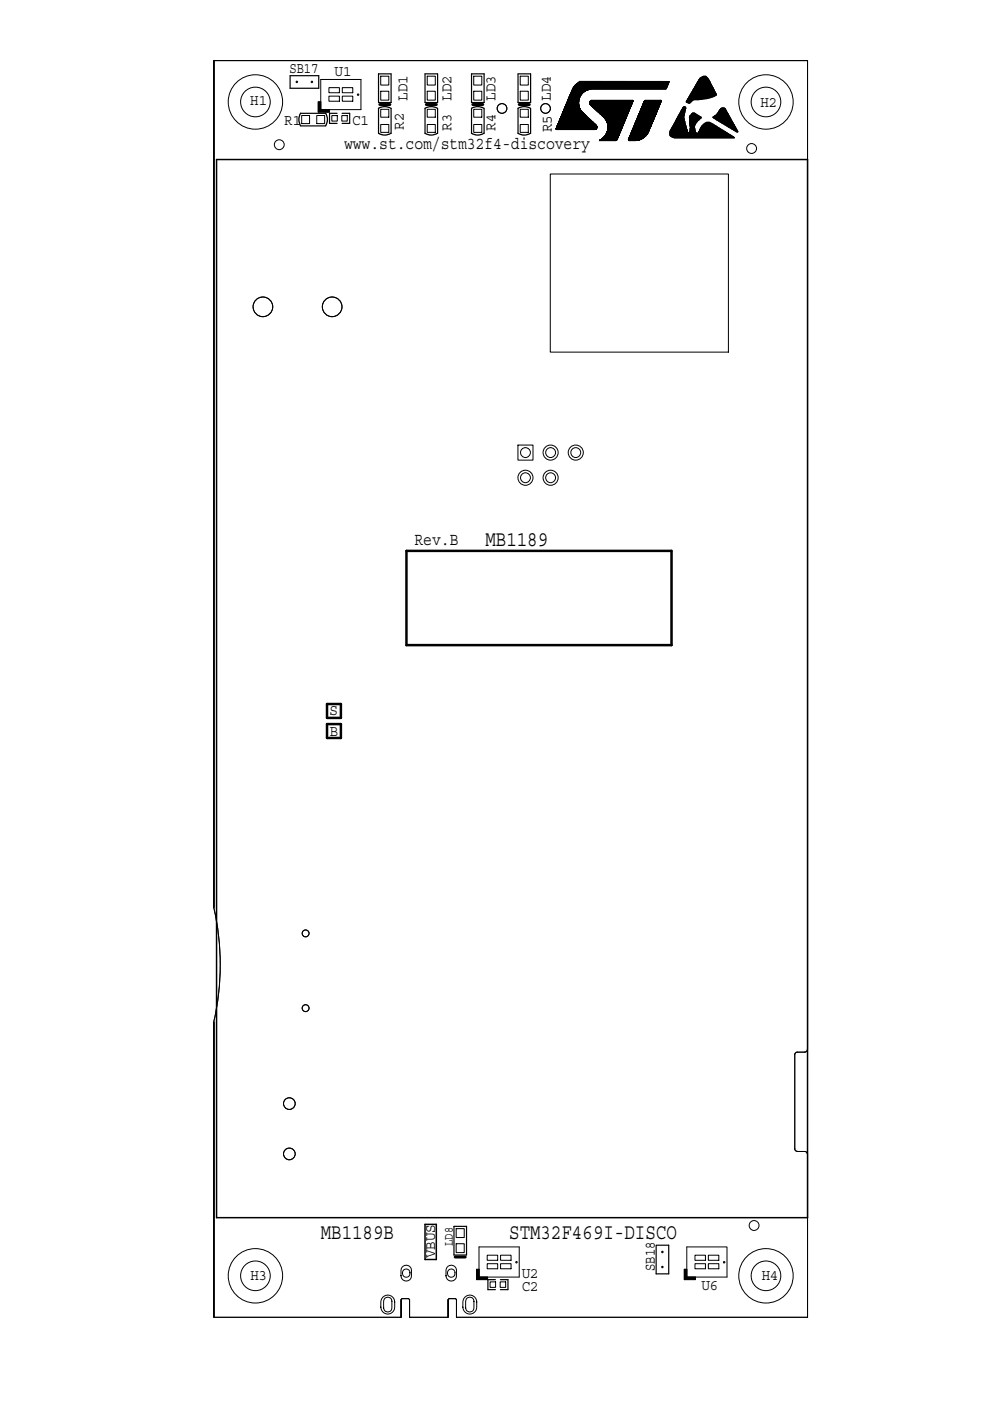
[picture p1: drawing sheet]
<svg xmlns="http://www.w3.org/2000/svg" width="210mm" height="297mm" viewBox="0 0 210 297" stroke-linecap="round" stroke-linejoin="round" font-family="sans-serif">
<defs><g id="words">
<g font-size="4.7">
<text x="103" y="115.7">MB1189</text>
<text x="68" y="262.8">MB1189B</text>
<text x="108" y="262.8">STM32F469I-DISCO</text>
</g>
<g font-size="3.8">
<text x="73" y="31.6">www.st.com/stm32f4-discovery</text>
<text x="87.9" y="115.5">Rev.B</text>
</g>
<g font-size="3.3">
<text x="61.4" y="15.5">SB17</text>
<text x="71" y="16">U1</text>
<text x="53.1" y="22.2">H1</text>
<text x="86.4" y="21.4" transform="rotate(-90 86.4 21.4)">LD1</text>
<text x="95.8" y="21.4" transform="rotate(-90 95.8 21.4)">LD2</text>
<text x="105.1" y="21.4" transform="rotate(-90 105.1 21.4)">LD3</text>
<text x="116.8" y="21.4" transform="rotate(-90 116.8 21.4)">LD4</text>
<text x="161.3" y="22.7">H2</text>
<text x="60.3" y="26.4">R1</text>
<text x="74.7" y="26.4">C1</text>
<text x="85.6" y="27.5" transform="rotate(-90 85.6 27.5)">R2</text>
<text x="95.8" y="27.8" transform="rotate(-90 95.8 27.8)">R3</text>
<text x="105.1" y="27.8" transform="rotate(-90 105.1 27.8)">R4</text>
<text x="117.1" y="28" transform="rotate(-90 117.1 28)">R5</text>
<text x="69.9" y="151.7">S</text>
<text x="69.9" y="156">B</text>
<text x="92.3" y="266.8" transform="rotate(-90 92.3 266.8)">VBUS</text>
<text x="138.9" y="269.5" transform="rotate(-90 138.9 269.5)">SB18</text>
<text x="53.1" y="271.3">H3</text>
<text x="110.7" y="271">U2</text>
<text x="110.7" y="273.7">C2</text>
<text x="148.8" y="273.4">U6</text>
<text x="161.6" y="271.3">H4</text>
</g>
<text font-size="2.8" x="96" y="264.1" transform="rotate(-90 96 264.1)">LD8</text>
</g></defs>
<g fill="none" stroke="#000" stroke-width=".21">
<path d="M45.4 12.8v179.6v-179.6M62.8 17.3h.3v.2h-.3zM66 17.3h.3v.2h-.3zM68 16.8h8.6v6.4h-8.6zM69.8 18.6h2.2v1.1h-2.2zM72.6 18.6h2.2v1.1h-2.2zM75.8 20h.3v.2h-.3zM80.8 19.3h1.7v1.9h-1.7zM80.8 16.2h1.7v1.8h-1.7zM90.6 19.3h1.7v1.9h-1.7zM90.6 16.2h1.7v1.8h-1.7zM100.5 19.3h1.7v1.9h-1.7z"/>
<path d="M100.5 16.2h1.7v1.8h-1.7zM110.3 19.3h1.8v1.9h-1.8zM110.3 16.2h1.8v1.8h-1.8zM121 20h.1M121.5 18.8h19.8M121.5 18.6h19.9M121.6 18.5h19.8M121.7 18.4h19.8M121.8 18.3h19.7M121.9 18.2h19.7M122 18.1h19.6M122.2 17.9h19.5"/>
<path d="M122.3 17.8h19.4M122.4 17.7h19.4M122.6 17.5h19.2M122.7 17.5h19.2M122.8 17.4h19.1M123.4 20h.1M123.4 19.9l-2.4 .1M123.4 19.9h-2.4M123.4 19.9h.1M123.5 19.9h.1M123.5 19.8l-2.5 .1M123.5 19.8h-2.4"/>
<path d="M123.5 19.8h.1M123.5 19.7h.1M123.6 19.7h-2.5M123.6 19.7h.1M123.7 19.6h.1M123.7 19.6h-2.6M123.8 19.6h-2.7M123.8 19.6h.1M123.8 19.5h-2.6M123.8 19.5h.1M123.9 19.5h.1M123.9 19.5h-2.7"/>
<path d="M124 19.4h.1M124 19.4h-2.8M124 19.3l-2.8 .1M124.1 19.3h.1M124.1 19.3h-2.9M124.2 19.3h.1M124.2 19.2l-2.9 .1M124.2 19.2h.1M124.3 19.2h.1M124.3 19.2h-3M124.4 19.2h.1M124.5 19.1l-3.2 .1"/>
<path d="M124.5 19.1h.1M124.6 19.1h.1M124.6 19.1h-3.3M124.7 19h.1M124.8 19l-3.5 .1M124.8 19h.1M124.9 19h.1M125 19h-3.6M125 19h.1M125.3 18.9h-3.9M141.3 18.9h-19.9M141.4 18.7h-19.9"/>
<path d="M141.4 18.6h-19.8M141.4 18.5l-19.8 .1M141.5 18.3h-19.7M141.6 18.2h-19.8M141.6 18.1l-19.7 .1M141.7 18h-19.7M141.7 17.9l-19.7 .1M141.7 17.9h-19.6M141.7 17.8h-19.5M141.8 17.7h-19.4M141.9 17.6h-19.4M141.9 17.3h-19"/>
<path d="M146.5 19.9h5.4l-5.4 .1h5.5v.2h-5.6M146.7 19.5h5l-5 .1 5 .1h-5.1l5.2 .1h-5.2h5.2M146.9 19.2h4.6l-4.6 .1h4.7h-4.8M147.1 18.9h4.3l-4.4 .1h4.4l-4.4 .1h4.5h-4.6M147.2 18.6l4.1 .1h-4.1M147.3 18.5h3.9l-3.9 .1M147.7 17.9h3.1h-3.2l3.3 .1-3.3 .1h3.3l-3.4 .1h3.5h-3.5M147.8 17.5h2.9l-2.9 .1M148.1 17.2h2.4l-2.5 .1 2.6 .1h-2.6l2.6 .1h-2.7M148.2 17l2.2 .1h-2.2M148.3 16.8l2 .1-2.1 .1h2.2M148.3 16.7l2 .1h-2"/>
<path d="M148.4 16.7h1.8M148.5 16.5l1.6 .1h-1.7h1.7M148.6 16.5h1.4M148.7 16.4h1.3M148.8 16.4h1.1M148.9 16.3h1M149 16.3h.8M149.1 16.2h.7M150.5 17.1h-2.4l2.4 .1M150.7 17.6l-2.9 .1h2.9M150.8 17.7h-3.1l3.1 .1M151 18.3h-3.6h3.6"/>
<path d="M151.1 18.4h-3.7l3.8 .1h-3.9M151.3 18.8h-4.1h4.1M151.6 19.4l-4.8 .1h4.8M171.3 12.8h-125.9h125.9M171.3 12.8v209.7M64 24.5h1.7v1.7h-1.7zM67.2 24.5h1.7v1.7h-1.7zM67.5 23.7h2.3M67.5 23.6h2.3M67.5 23.5h2.3M67.5 23.4h2.3M67.5 23.3h2.3"/>
<path d="M67.5 23.2h.5M67.5 23.1h.5M67.5 23h.5M67.5 22.9h.5M67.5 22.8h.5M67.5 22.7h.5M67.5 22.6h.5M67.5 22.5h.5M67.5 22.4h.5M67.5 22.3h.5M67.5 22.2h.5M67.5 22.1h.5"/>
<path d="M67.5 22h.5M67.5 21.9h.5M67.5 21.8h.5M67.5 21.7h.5M67.5 21.6h.5M68 23.2v-1.6h-.5v2.1h2.3v-.5h-2.3M69.8 20.4h2.2v1.1h-2.2zM70.4 24.5h1.1v1.2h-1.1zM72.5 24.5h1.2v1.2h-1.2zM72.6 20.4h2.2v1.1h-2.2zM80.8 23.2h1.7v1.6h-1.7zM80.8 26.4h1.7v1.7h-1.7z"/>
<path d="M90.6 23.2h1.7v1.6h-1.7zM90.6 26.4h1.7v1.7h-1.7zM100.5 23.2h1.7v1.6h-1.7zM100.5 26.4h1.7v1.7h-1.7zM110.3 23.2h1.8v1.6h-1.8zM110.3 26.4h1.8v1.7h-1.8zM116.7 36.9h37.8v37.8h-37.8zM118 27.2h8.6M118 27.4h8.4M118 27.3h.1M118 27.2h.1M118 27.4h.1"/>
<path d="M118 27.5h8.3M118 27.1h8.6M118 27h8.6M118.1 26.9h8.5M118.1 27h.1M118.1 26.9h.1M118.1 26.8h8.5M118.2 26.7h8.4M118.2 26.8h.1M118.2 26.7h.1M118.2 26.6h8.3M118.2 26.6h.1"/>
<path d="M118.3 26.5h8.1M118.3 26.5h.1M118.3 26.4h.1M118.3 26.4h8M118.3 26.3h7.9M118.4 26.2l7.8 .1M118.4 26.3h.1M118.4 26.2h.1M118.4 26.2h7.6M118.4 26.2h7.7M118.4 26.1h7.5M118.5 26h7.3"/>
<path d="M118.5 26h.1M118.5 25.9l7.3 .1M118.5 25.8h7.2M118.5 25.9h7.2M118.6 25.7h7M118.6 25.8h7M118.6 25.8h.1M118.6 25.7h.1M118.6 25.7h6.9M118.6 25.6h6.9M118.7 25.5h6.6M118.7 25.5l6.7 .1"/>
<path d="M118.7 25.5h.1M118.7 25.4h6.5M118.7 25.4h.1M118.7 25.3l6.5 .1M118.8 25.3h6.3M118.8 25.2h6.2M118.8 25.2l6.3 .1M118.8 25.3h.1M118.8 25.2h.1M118.8 25.1h6.1M118.8 25.1h.1M118.9 25.1h6"/>
<path d="M118.9 25h5.9M118.9 24.9h5.8M119 24.8h5.6M119 24.7l5.5 .1M119 24.7h5.5M119 24.7h.1M119 24.6l5.4 .1M119.1 24.6h5.2M119.1 24.6h5.3M119.1 24.5h5.1M119.1 24.5h.1M119.1 24.4l5.1 .1"/>
<path d="M119.1 24.4h.1M119.1 24.4h5M119.2 24.3l4.9 .1M119.2 24.3h4.8M119.2 24.3h.1M119.2 24.2h4.7M119.2 24.2h.1M119.3 24.1h4.6M119.3 24.1h4.5M119.3 24h4.5M119.3 24h4.4M119.3 24h.1"/>
<path d="M119.3 23.9h4.4M119.3 23.9h.1M119.4 23.9h4.2M119.4 23.8h4.1M119.4 23.7l4.1 .1M119.4 23.8h.1M119.4 23.7h4M119.4 23.7h.1M119.5 23.6h3.8M119.5 23.5h3.8M119.5 23.5h.1M119.5 23.4h3.7"/>
<path d="M119.5 23.5h3.7M119.5 23.4h.1M119.6 23.3h3.5M119.6 23.2h3.5M119.6 23.3h.1M119.6 23.2h.1M119.7 23.2h.1M119.7 23.2h3.4M119.7 23.1h3.3M119.7 23h3.3M119.7 23.1h.1M119.7 23h.1"/>
<path d="M119.8 22.9h.1M119.8 22.9h3.1M119.8 22.8h3.1M119.8 22.8h.1M119.8 22.7h.1M119.8 22.7h3.1M119.9 22.7h.1M119.9 22.6h.1M119.9 22.6h3M119.9 22.6h2.9M119.9 22.5h2.9M119.9 22.5h.1"/>
<path d="M120 22.5h2.8M120 22.4h2.8M120 22.3h2.8M120 22.2l2.8 .1M120 22.3h.1M120.1 22.2h2.6M120.1 22.1h2.6M120.1 22h2.6M120.1 22h.1M120.2 22h2.5M120.2 21.9h2.5M120.2 21.8h2.5"/>
<path d="M120.2 21.7h2.5M120.2 21.8h.1M120.3 21.7h2.4M120.3 21.6h2.4M120.3 21.5h2.4M120.4 21.5h.1M120.4 21.4h2.3M120.4 21.5h2.3M120.4 21.4h2.4M120.4 21.3h2.4M120.4 21.3h.1M120.4 21.2h2.4"/>
<path d="M120.5 21.3h.1M120.5 21.2h.1M120.5 21.2h2.3M120.5 21.1h2.3M120.5 21h2.3M120.5 21.1h.1M120.5 21h.1M120.6 21h2.2M120.6 21h.1M120.6 20.9h2.3M120.6 20.9h.1M120.6 20.8h2.3"/>
<path d="M120.6 20.8h.1M120.7 20.7h2.2M120.7 20.8h.1M120.7 20.7h.1M120.7 20.6h2.3M120.7 20.5h2.3M120.8 20.5h.1M120.8 20.6h.1M120.8 20.5h2.2M120.8 20.4h2.3M120.8 20.3h2.3M120.9 20.3h.1"/>
<path d="M120.9 20.2h.1M120.9 20h2.4M121 20.1h.1M122.7 21.8h.1M122.7 21.7h.1M122.7 22h.1M122.7 21.9h.1M122.7 21.6h.1M122.7 21.5h.1M122.7 22.2h.1M122.7 22.1h.1M122.7 21.6l-2.4 .1"/>
<path d="M122.7 21.4h.1M122.8 22.4h-2.8M122.8 22.5h.1M122.8 22.4h.1M122.8 21.2h.1M122.8 21.1h.1M122.8 21.1h-2.3M122.8 22.6h.1M122.8 21h.1M122.9 21h-2.3M122.9 22.7h.1M122.9 22.6h.1"/>
<path d="M122.9 21h.1M122.9 20.9h.1M122.9 20.9h-2.3M122.9 22.9h.1M122.9 22.8h.1M122.9 20.8h.1M122.9 20.7h.1M123 20.7h-2.3M123 20.6h-2.3M123 20.6h.1M123 23.1h.1M123 20.5h.1"/>
<path d="M123 23.2h.1M123.1 20.3h.1M123.1 23.3h.1M123.2 20.3h-2.4M123.2 20.2h-2.3M123.2 20.2h.1M123.2 23.5h.1M123.3 20.1h.1M123.3 23.5h.1M123.3 20.1h-2.4M123.3 20l-2.4 .1M123.3 20h.1"/>
<path d="M123.3 23.6h.1M123.4 23.6h.1M123.4 23.7h.1M123.5 23.8h.1M123.6 23.9h.1M123.7 23.9h.1M123.7 24h.1M123.8 24h.1M123.8 24.1h.1M123.9 24.1h.1M124 24.2h.1M124.1 24.3h.1"/>
<path d="M124.1 24.4h.1M124.2 24.4h.1M124.2 24.5h.1M124.3 24.5h.1M124.4 24.6h.1M124.9 25.1h.1M125 25.1h.1M125 25.2h.1M125.1 21.8h9M125.1 21.8h.1M125.1 21.9h.1M125.1 21.9h9"/>
<path d="M125.1 25.3h.1M125.1 21.7h9.1M125.1 22h8.9zM125.1 22h8.9M125.1 21.9h8.9M125.1 21.6h9.1M125.1 22.1h8.9M125.2 22.1h8.8M125.2 21.5h.1M125.2 22.1h.1M125.2 25.4h.1M125.2 21.5h9"/>
<path d="M125.2 21.4h9.1M125.2 22.2h8.8M125.2 22.2h8.7M125.3 22.2h8.6M125.3 22.2h.1M125.3 25.4h.1M125.3 21.4h8.9M125.3 22.3h8.6M125.3 25.5h.1M125.3 21.3h8.9M125.4 22.4h8.5h-8.5M125.4 21.3h.1"/>
<path d="M125.4 22.4h.1M125.4 25.5h.1M125.4 25.6h.1M125.4 22.4h8.5M125.5 21.3h8.7M125.5 22.5h8.3M125.5 21.3h.1M125.5 25.7h.1M125.5 22.5h.1M125.6 22.5h8.2M125.6 22.5h.1M125.6 22.6h8.2h-8.2"/>
<path d="M125.6 25.8h.1M125.7 22.6h8.1M125.7 22.6h.1M125.7 25.8h.1M125.7 22.7h8.1M125.7 25.9h.1M125.8 22.7h8M125.8 22.7h7.9M125.8 22.7h.1M125.8 25.9h.1M125.8 22.8h7.9M125.8 26h.1"/>
<path d="M125.8 22.8h7.9h-7.8M125.9 22.8h7.8zM125.9 26h.1M125.9 26.1h.1M126 22.9h7.7M126 22.9l7.6 .1zM126 22.9h.1M126 26.1h.1M126.1 23h7.5M126.1 23.1h7.5zM126.1 23h.1M126.1 26.2h.1"/>
<path d="M126.2 23.1h7.4M126.2 23.1h.1M126.2 26.3h.1M126.2 27.5h.1M126.2 23.2h7.4M126.2 26.4h.1M126.3 23.2h7.2M126.3 26.4h.1M126.3 23.2h.1M126.3 26.5h.1M126.3 27.4h.1M126.4 23.3h7.1"/>
<path d="M126.4 26.5h.1M126.4 27.4h.1M126.4 23.3h.1M126.4 26.6h.1M126.5 27.3l-8.5 .1M126.5 23.4h7M126.5 27.3h-8.5M126.5 26.6h.1M126.5 27.3h.1M126.5 23.4h.1M126.5 26.7h.1M126.6 27.2l-8.6 .1"/>
<path d="M126.6 27.2h.1M126.6 23.5h6.8M126.6 26.7h.1M126.6 26.9h-8.5M126.6 26.8h.1M126.6 27.1h.1M126.6 27h.1M126.6 26.9h.1M126.6 23.5h.1M126.7 23.6h6.7M126.7 23.6h6.7h-6.7M126.7 23.6h.1"/>
<path d="M126.8 23.6h6.5M126.8 23.7h6.5M126.8 23.7h.1M126.9 23.7h6.4M126.9 23.8h6.4M126.9 23.8h.1M127 23.8h6.3M127 23.9h6.3M127.1 23.9h6.1M127.1 24h6.1M127.1 24h.1M127.2 24h6"/>
<path d="M127.2 29.8h3.5M127.2 29.8h3.4M127.2 24.1h6M127.2 24.1h.1M127.2 29.8h.1M127.3 24.1h.1M127.3 29.7h.1M127.3 24.1h5.9M127.3 24.1h5.8M127.3 24.2h5.8M127.3 24.2h.1M127.4 24.2h5.7"/>
<path d="M127.4 29.6h3.4l-3.5 .1M127.4 24.3h5.7M127.4 24.3h5.7zM127.4 29.6h.1M127.5 24.3h5.6M127.6 24.4h5.4zM127.6 24.4h.1M127.6 29.5h.1M127.6 29.5h3.3M127.6 24.4h5.4M127.7 29.4h.1M127.7 24.5h5.3z"/>
<path d="M127.7 24.5h.1M127.7 29.4h3.2h-3.3M127.7 24.5h5.3M127.7 29.4h3.3M127.8 24.6h.1M127.8 29.4h.1M127.8 24.6h5.1h-5.1M127.8 24.6h5.1M127.8 29.3h3.2M127.9 24.6h.1M127.9 29.3h.1M127.9 24.7h5"/>
<path d="M127.9 29.3h3.1M128 29.2h.1M128 29.2h3.1M128 24.7h.1M128 24.7h4.9M128 24.8h4.9M128 29.1h3.1M128.1 24.8h.1M128.1 29.1h.1M128.1 24.8l4.7 .1h-4.7M128.1 29l3 .1h-3M128.1 24.9h4.7"/>
<path d="M128.2 29h.1M128.2 24.9h.1M128.2 29h2.9M128.2 25h4.6M128.2 28.9h3M128.2 25.1h4.6M128.3 25.1h.1M128.3 25h.1M128.3 28.9h.1M128.3 25.1h4.4M128.3 28.8h2.9M128.3 25.2h4.4"/>
<path d="M128.3 28.7h2.9M128.4 25.2h.1M128.4 28.7h.1M128.4 25.2h4.3M128.4 28.7h2.8M128.4 28.7h2.9M128.4 25.3h4.3M128.4 28.6h2.9M128.5 28.5h2.8zM128.5 28.6h.1M128.5 25.4h.1M128.5 25.4h4.1"/>
<path d="M128.5 28.5h2.8M128.5 25.5h4.1M128.6 28.4h2.8M128.6 28.4h.1M128.6 25.5h.1M128.6 25.6h3.9M128.6 28.3h2.8M128.7 28.2h2.7M128.7 28.2h.1M128.7 28.1h2.8M128.7 25.7h.1M128.7 25.8h3.8"/>
<path d="M128.7 25.8h3.7M128.7 25.9h3.7M128.8 27.9h2.8M128.8 25.9h3.6M128.8 28h.1M128.8 27.9h.1M128.8 25.9h.1M128.8 26h3.6M128.8 27.8h2.8M128.8 26.1h3.5M128.9 27.6h2.8M128.9 26.2l3.3 .1h-3.3"/>
<path d="M128.9 26.2h3.4M128.9 27.7h.1M128.9 27.6h.1M128.9 26.2h.1M128.9 27.5h2.8M128.9 26.3h3.3M128.9 26.5h3.2M128.9 27.3h2.9M128.9 26.4h3.3M128.9 27.2h2.9M128.9 27.2h3M128.9 26.8h3.2"/>
<path d="M128.9 26.6h3.2M128.9 26.7h3.2M129 27h3M129 26.9h3M129 27.1h2.9M129 26.8h3M129 27.1h.1M129 27h.1M129 26.9h.1M129 26.8h.1M130.5 29.8h.1M130.6 29.8h.1"/>
<path d="M130.7 29.7h.1M130.8 29.7h.1M130.8 29.7h-3.6M130.9 29.7h.1M130.9 29.6h.1M130.9 29.6h-3.5M130.9 29.5h-3.4M130.9 29.5h.1M131 29.4h.1M131 29.3h.1M131 29.3h-3.2h3.2M131 29.2h.1"/>
<path d="M131.1 29.2h-3.2M131.1 29.1h.1M131.1 29.2h.1M131.1 29h-3M131.1 29h.1M131.2 28.9h.1M131.2 28.9h-3M131.3 28.7h.1M131.3 28.6h-2.9M131.4 28.5h.1M131.4 28.4h.1M131.4 28.4h-2.9"/>
<path d="M131.5 28.2h.1M131.5 28l-2.8 .1M131.6 28h-2.8M131.6 28h.1M131.6 27.9h.1M131.7 27.8h.1M131.7 27.7h.1M131.7 27.7h-2.9M131.7 27.6h.1M131.8 27.5h-2.9h2.8M131.8 27.5h.1M131.8 27.4h.1"/>
<path d="M131.8 27.4h-2.9h2.9M131.9 27.3h.1M131.9 27.2h.1M131.9 27.1h.1M131.9 27.1h-3M132 27h.1M132 26.9h.1M132 26.9h-3M132.1 26.8h.1M132.1 26.7h.1M132.1 26.6l-3.2 .1M132.1 26.5l-3.2 .1"/>
<path d="M132.2 26.5h.1M132.2 26.4h.1M132.2 26.4h-3.3l3.3 .1M132.2 26.4h-3.3h3.3M132.3 26.2h.1M132.3 26.1h-3.5M132.4 26h.1M132.4 25.9h.1M132.5 25.8h.1M132.5 25.7h.1M132.5 25.7h-3.8M132.5 25.6h.1"/>
<path d="M132.6 25.5h.1M132.6 25.4h.1M132.7 25.3l-4.2 .1M132.7 25.3h.1M132.7 25.2h.1M132.8 25h.1M132.8 24.9h.1M132.9 24.7h.1M133 24.5h.1M133 24.4h.1M133.1 24.3h.1M133.1 24.2h.1"/>
<path d="M133.1 24.1h.1M133.2 24.1h.1M133.2 24h.1M133.2 23.9h.1M133.3 29.7h2.2M133.3 23.8h.1M133.3 29.7h.1M133.3 29.6h.1M133.3 23.7h.1M133.3 29.7h2M133.3 29.7h2.1M133.3 29.5h2.7"/>
<path d="M133.3 29.8h1.9M133.3 29.5h2.8M133.4 29.8h1.6M133.4 29.4h.1M133.4 29.3h.1M133.4 23.5h.1M133.4 23.4h.1M133.5 29.8h1.2M133.5 23.4h.1M133.5 29.1h.1M133.5 23.3h.1M133.5 23.2h.1"/>
<path d="M133.6 28.8h3.4zM133.6 23h.1M133.6 28.8h.1M133.6 22.9h.1M133.7 28.7h3.4M133.7 28.6h3.5M133.7 28.5h3.5zM133.7 22.8h.1M133.7 28.6h.1M133.8 22.7h.1M133.8 22.6h.1M133.8 28.5h3.4"/>
<path d="M133.8 28.3h3.5M133.8 28.3h3.6M133.8 28.2h3.6zM133.8 22.5h.1M133.8 28.3h.1M133.9 22.4h.1M133.9 28.2h3.5h-3.5M133.9 28.1h3.6M133.9 22.3h.1M133.9 28.1h.1M133.9 28h3.6M133.9 22.2h.1"/>
<path d="M134 22.2h.1M134 28h3.5M134 27.9h3.5M134 27.9h3.6M134 27.9h.1M134 27.8h.1M134 22.1h.1M134 22h.1M134 21.9h.1M134.1 27.7h3.5M134.1 21.9h.1M134.1 27.7h3.6"/>
<path d="M134.1 27.6h3.6M134.1 21.8l-9 .1M134.1 21.8h.1M134.1 27.6h.1M134.2 21.7l-9.1 .1M134.2 21.3h.1M134.2 21.7h.1M134.2 27.6h3.5M134.2 27.5h3.5M134.2 27.4h3.6M134.2 27.3h3.6M134.2 21.5h-9.1"/>
<path d="M134.2 27.3h3.7zM134.2 21.4h.1M134.2 21.5h.1M134.2 27.3h.1M134.3 21.4h.1M134.3 27.3h3.5h-3.6M134.3 27.2h3.6M134.3 27.1h3.6M134.3 27.1h.1M134.4 27.1h3.5M134.4 27h3.5M134.4 27h3.6"/>
<path d="M134.4 26.9h3.6M134.4 26.8h3.6M134.5 26.8h.1M134.5 26.8h3.5M134.5 26.7h3.6M134.5 26.6h3.6M134.6 26.5l3.6-.1zM134.6 26.6h.1M134.6 26.5h3.5M134.6 26.4h3.6M134.6 26.3h3.6M134.7 26.3h.1"/>
<path d="M134.7 26.2h3.6M134.7 26.1h3.6M134.7 29.8h.1M134.7 26.1h.1M134.8 26l3.6-.1zM134.8 26.1h.1M134.8 26h3.5M134.8 25.8h3.6M134.8 25.9h3.6M134.9 25.9h.1M134.9 25.8h.1M134.9 25.8h3.5"/>
<path d="M134.9 25.8h3.6M134.9 25.6h3.6M134.9 25.7h3.6M135 25.6h.1M135 25.5h3.6zM135 25.5h3.5M135 25.3h3.6M135.1 25.3l3.6-.1zM135.1 25.3h.1M135.1 29.8h.1M135.1 25.4h.1M135.1 25.3h3.5"/>
<path d="M135.1 25.1h3.6M135.2 25h3.6zM135.2 25.1h.1M135.2 25h3.5M135.2 24.9h3.6M135.3 24.8h.1M135.3 24.8h3.6M135.3 24.7h3.6M135.3 24.6h3.6M135.4 24.6h.1M135.4 24.5h3.6M135.4 24.4h3.6"/>
<path d="M135.5 24.4h.1M135.5 29.7h.1M135.5 24.3h3.6M135.5 24.3h.1M135.6 24.1h3.5M135.6 24.1h.1M135.6 24h3.6zM135.6 24.1h3.5h-3.5M135.6 24h3.6M135.7 23.9h.1M135.7 23.8h3.6M135.7 29.6h.1"/>
<path d="M135.7 29.6l-2.4 .1M135.7 23.7h3.6M135.8 23.6h.1M135.8 29.6h.1M135.8 23.5h3.6M135.8 29.6h-2.5M135.9 23.3h3.5M135.9 23.4h.1M135.9 23.3h.1M135.9 23.3h3.6h-3.6M135.9 29.5h.1M135.9 23.3h3.6"/>
<path d="M135.9 23.2h3.6M136 29.5h-2.7h2.6M136 23.2h3.5M136 23.1h3.6M136 23.1h.1M136 23.1h3.6h-3.6M136 29.5h.1M136.1 22.9h3.5M136.1 22.9h3.6M136.1 22.8h.1M136.1 22.8h3.6h-3.6M136.1 22.8h3.6"/>
<path d="M136.1 29.4h.1M136.1 22.7h3.6M136.2 29.4h-2.9h2.8M136.2 29.4h.1M136.2 22.6h.1M136.2 22.6h3.6M136.2 22.5h.1M136.2 22.5h3.6h-3.6M136.2 22.5h3.6M136.2 22.4h3.6M136.3 29.4h-2.9M136.3 29.4h.1"/>
<path d="M136.3 22.4h.1M136.3 29.3h.1M136.3 22.3h.1M136.3 22.3h3.6M136.3 22.2h3.6M136.4 22.2h3.5M136.4 22.2h3.6M136.4 29.3h-3M136.4 22.1h.1M136.4 29.3h.1M136.4 22.1h3.6M136.4 29.3h-3h3"/>
<path d="M136.5 21.9h3.5M136.5 21.9h3.6M136.5 21.8l3.6-.1zM136.5 21.9h.1M136.5 29.2h-3.1h3.1M136.5 21.8h3.6M136.5 29.2h.1M136.6 29.1l-3.2 .1h3.1M136.6 21.7h3.6M136.6 21.7h3.5M136.6 21.6h3.6M136.6 21.6h.1"/>
<path d="M136.6 21.5h3.6M136.6 29.1h.1M136.7 29.1h-3.2M136.7 21.5h3.5M136.7 21.4h3.5M136.7 29l-3.2 .1M136.7 21.4h.1M136.7 29h.1M136.8 29h-3.3h3.3M136.8 21.3h3.4M136.8 21.3h.1M136.8 29h.1"/>
<path d="M136.8 28.9h.1M136.8 28.9l-3.2 .1M136.9 28.9h-3.3M136.9 21.3h3.2M136.9 21.3h.1M136.9 28.9h.1M136.9 28.8l-3.3 .1M136.9 28.8h.1M137 28.8h.1M137 28.7h.1M137.1 28.7h-3.5h3.4M137.1 28.7h.1"/>
<path d="M137.1 28.6h.1M137.1 28.6l-3.4 .1M137.2 28.6h.1M137.2 28.5h.1M137.3 28.4h-3.5M137.3 28.4h.1M137.4 28.3h.1M137.4 28.2h.1M137.5 28.1h.1M137.5 28.1l-3.6 .1M137.5 28h.1M137.5 27.9h.1"/>
<path d="M137.6 27.9h.1M137.6 27.9h-3.6M137.6 27.8h-3.6M137.6 27.8h.1M137.6 27.7h.1M137.7 27.7h.1M137.7 27.6h.1M137.7 27.5h.1M137.8 27.5h.1M137.8 27.5h-3.6h3.5M137.8 27.4h.1M137.9 27.2h-3.6"/>
<path d="M138 27h.1M138 26.9h.1M138 26.9h-3.6M138 26.8h.1M138.1 26.7h.1M138.1 26.7h-3.6M138.1 26.5l-3.6 .1M138.2 26.5h.1M138.2 26.4h.1M138.2 26.4h-3.6M138.3 26.3h.1M138.3 26.2h-3.6l3.5 .1"/>
<path d="M138.3 26.2h.1M138.3 26l-3.6 .1M138.4 26h.1M138.5 25.8h.1M138.5 25.7h.1M138.5 25.7h-3.6h3.6M138.6 25.5h.1M138.6 25.6h.1M138.6 25.4l-3.6 .1M138.6 25.4h.1M138.6 25.4h-3.6M138.7 25.3h.1"/>
<path d="M138.7 25.2h.1M138.7 25.1h.1M138.7 25.2h-3.6M138.7 25.1h-3.6M138.8 25h.1M138.8 24.8l-3.6 .1M138.9 24.8h-3.6M138.9 24.8h.1M138.9 24.7h.1M138.9 24.6l-3.6 .1M139 24.5l-3.6 .1M139 24.5h.1"/>
<path d="M139.1 24.3h.1M139.1 24.2h.1M139.1 24.2h-3.6M139.2 24h.1M139.2 23.9h.1M139.2 23.9h-3.6M139.3 23.9h-3.6M139.3 23.9h.1M139.3 23.8h.1M139.3 23.7h.1M139.3 23.6l-3.6 .1M139.4 23.6h-3.6"/>
<path d="M139.4 23.6h.1M139.4 23.5h-3.6l3.6 .1M139.4 23.5h.1M139.4 23.4h.1M139.4 23.4h-3.6M139.5 23.3h.1M139.5 23.2h.1M139.6 23.1h.1M139.6 23h.1M139.6 23h-3.6h3.6M139.6 22.9l-3.6 .1M139.7 22.8h.1"/>
<path d="M139.7 22.7h.1M139.7 22.7h-3.6M139.8 22.6h-3.6M139.8 22.5h.1M139.9 22.4h-3.6M139.9 22.3h-3.6M139.9 22.3h.1M139.9 22.2h.1M140 22.1h-3.6M140 22.1h.1M140 22h.1M140 22h-3.6h3.6"/>
<path d="M140 21.9h.1M140.1 21.8l-3.6 .1M140.1 21.8h.1M140.1 21.3h.1M140.1 21.7h.1M140.2 21.3h.1M140.2 21.6h.1M140.2 21.5h.1M140.2 21.4h.1M142 28.2h5.8M142 28.6h12.9M142 28.2h12.3"/>
<path d="M142 28.4h12.6M142 27.9h3.8M142 28h3.9M142 28.1h5.6M142 28.6h13M142 28.5h12.8M142 28.3h12.5M142 28.1h3.9M142 28.5h12.7M142.1 27.9h3.7M142.1 27.8h3.7v.2h-3.8M142.1 28.7h13.1"/>
<path d="M142.1 28.7h12.9M142.2 27.7h3.6M142.2 28.8h13.1M142.2 27.6h3.6v.2h-3.6l3.6-.1M142.2 28.9h13.2M142.3 28.9h13.2M142.3 27.5l3.4 .1h-3.4M142.3 27.5h3.4M142.4 27.3l3.3 .1h-3.4M142.4 29h13.2M142.4 27.2l3.2 .1h-3.2M142.5 29h13.1"/>
<path d="M142.5 27.1h3.1l-3.1 .1M142.5 27h3.1h-3.1M142.5 27.1h3.1M142.6 29.1h13.1M142.6 26.9h2.9M142.7 26.8l2.8 .1h-2.9M142.7 29.1h13l-12.8 .1M142.7 26.6l2.8 .2M142.9 26.3l2.5 .1-2.5 .1M143 26.2l2.4 .1M143 29.3h12.7M143.1 26.1h2.2l-2.3 .1"/>
<path d="M143.3 25.7h1.9v.2l-2.1 .1M143.3 25.7h.1M143.3 25.5l1.9 .1h-1.9M143.4 25.4h1.7M143.4 25.4h.1M143.6 25.1h1.5h-1.6l1.6 .2h-1.6h1.6v.2M143.7 24.8h1.3h-1.3l1.3 .1h-1.3M143.8 24.7h1.2h-1.2M144.1 24.2h1.1l-1.1 .1h1.1M144.3 23.8h.9v.1h-1l1 .1-1 .1h1M144.7 23.1h.8M144.8 23h.7h-.7"/>
<path d="M144.8 22.8l.7 .1M144.9 22.7l.5 .1h-.5M145 22.6h.4M145 22.6h.3M145 25h-1.4h1.5M145.1 24.5h-1.2l1.2 .1h-1.3h1.3M145.1 24.3l-1.1 .1M145.2 23.8h-.9l.9 .1M145.2 25.8h-2M145.3 23.5l-.9 .1 .8 .1h-.8M145.4 23.3l-.9 .2M145.4 23.1h-.7l.7 .1-.8 .1h.8"/>
<path d="M145.5 26.5v.1M145.5 26.5l-2.8 .1M145.6 21.7h.9M145.6 21.4h1.2M145.7 21.7h.8M145.8 21.2h2.5M145.8 21.8h.6M145.9 21.8h.5M146 20.8h4.6M146 20.7h4.7M146.1 21.9h.2M146.1 20.7h4.7"/>
<path d="M146.2 20.5h5.1M146.2 24.8l2.5 .1h-2.5M146.3 24.8h2.4M146.3 25.6h.1M146.3 25.9h1.5M146.3 25.5h1.9M146.3 25.3h2.1M146.3 25.2h2.2M146.3 25.4h.1M146.3 25.5h.1M146.3 25.1h2.4M146.3 25.1h2.3"/>
<path d="M146.3 27.9h1.2h-1.2M146.3 26.3h1.2M146.3 26.2l1.2 .1M146.3 26.3v.1M146.3 26.4v.1M146.4 24.5h1.8M146.4 27.6h1h-1v.2h1M146.4 27.7h1h-1M146.4 26.7h.9v.2h-.9h.9M146.4 26.6v.1M146.4 26.8h.1M146.4 24.5h1.7"/>
<path d="M146.4 27h.9v.2l-.9 .1h1v.2h-1h1M146.5 24.4h1.6M146.5 24.4h1.5M146.6 24.3h1.2M146.6 24.3h1.1M146.6 21.6h-1h1M146.7 24.1h.8M146.7 21.5h-1.1h1.1M146.8 24h.6M146.9 23.9h.4M146.9 21.3h-1.2l1.1 .1M147 21.2h-1.3l1.3 .1"/>
<path d="M147.3 27l-.9 .1h.9M147.3 27.1l-.9 .1h.9M147.3 26.8h-.9M147.4 26.5h-1.1M147.4 27.3l-1 .1h1M147.4 26.4h-1.1M147.5 27.8h-1.2v.2h1.2l-1.2 .1h1.3M147.5 26.2v.1M147.6 24.2h-.9h1M147.6 26.1v.1M147.7 26l-1.4 .1M147.9 25.8h-1.6"/>
<path d="M148 25.7h-1.7v.4h1.3M148 28.2h6.3M148.1 25.6h-1.8M148.1 28.1h6.1M148.1 28.1h6M148.3 24.6h-2h2.1M148.3 27.8h5.4M148.3 25.4h-2M148.4 24.7h-2.1h2.2M148.4 27.6h4.9M148.7 27.1h3.8M148.7 24.9h-2.4l2.4 .1h-2.4v.3h2.1"/>
<path d="M148.8 26.8h3.2M148.8 26.8h.1M148.9 26.7h3M149 21.1h-3.2h2.9M149 26.6h2.7M149.1 26.5h2.4M149.2 26.4h2.2M149.3 26.3h1.9M149.5 26.2h1.4M149.6 26.1h1.2M149.8 26h.8M149.9 21h-4h3.5"/>
<path d="M150.3 20.8h-4.4l4.2 .1M151.2 20.6h-5.1h4.9M151.3 24.8h3.5l-3.6 .1h3.6h-3.5M151.3 25h3.6M151.4 25h3.5l-3.5 .1M151.4 24.7h3.3h-3.4M151.5 24.6h3.2M151.5 25.1h3.5l-3.4 .1M151.6 20.4h-5.4l5.2 .1M151.6 24.5l3 .1h-3.1M151.7 20.3h-5.4l5.3 .1M151.7 24.5h2.9"/>
<path d="M151.7 25.3h3.3M151.8 25.3h3.2M151.8 25.4h3.4M151.8 24.4h2.8h-2.8M151.9 20.2h-5.6l5.5 .1M152 20h-5.6l5.6 .1M152 24.3h2.5M152 25.5h3.2M152.2 26.9h-3.4h3.4M152.2 25.6h3M152.2 24h2.1l-2.1 .1 2.2 .1h-2.3l2.4 .1h-2.5M152.3 27h-3.6h3.7"/>
<path d="M152.3 23.8l1.9 .1h-1.9h2M152.4 25.7l2.9 .1M152.5 23.6h1.6M152.5 27.1l-3.9 .1h4.1M152.6 25.8l2.8 .1M152.7 23.2l1.2 .1h-1.2M152.8 25.9l2.6 .1M152.8 27.2l-4.3 .1h4.3M152.9 23h.9l-1 .1 1.1 .1h-1.1M152.9 27.3l-4.4 .1h4.5M152.9 23h.9M153 26l2.5 .1"/>
<path d="M153 22.9h.7M153.1 27.5h-4.7h4.7M153.1 26.1h2.4M153.1 22.9h.5M153.3 26.2l2.3 .1M153.4 27.6l-5 .1h5M153.5 26.3l2.2 .1M153.5 27.7l-5.2 .1h5.3M153.7 26.4l2 .1h-1.9M153.8 27.9h-5.6h5.7M153.9 28h-5.7h5.8M154 26.6l1.9 .2"/>
<path d="M154 23.3h-1.4l1.4 .2h-1.5h1.5M154.1 23.6l-1.7 .1h1.7M154.2 23.7h-1.8l1.8 .1M154.2 26.8h1.7l-1.6 .1M154.5 26.9h1.5l-1.5 .1M154.6 27h1.4M154.7 27.1h1.4h-1.3M154.9 27.2h1.2h-1.1M155 27.3h1.2h-1M155.2 25.5h.1M155.2 27.4h1M155.2 25.6h.1"/>
<path d="M155.3 27.5h1h-.9M155.5 27.6h.8M155.5 26.1v.1M155.6 26.2v.1M155.6 27.6h.7l-.6 .1M155.8 27.7h.6M155.9 27.8h.5M156 27.8h.5v.2h-.3M156.1 27.9h.4M156.3 28h.1M109.9 94.4h3.2v3.2h-3.2zM45.3 192.4a54.1 54.1 0 0 1 0 24.3"/>
<path d="M45.4 216.7v62.6v-62.6M170.7 223.1h-1.6l-.5 .2v.3v20M171.2 222.5l-.2 .5-.3 .1M168.6 243.6l.2 .4 .3 .1M169.1 244.1h1.6M170.7 244.1l.3 .1 .2 .4M45.4 279.3h39.7M81.2 275a1.48 1.48 0 0 1 1.6-.3 1.48 1.48 0 0 1 .9 1.4 2.11 2.11 0 0 1-.7 2.3 1.48 1.48 0 0 1-2.2-1.3v-1.4zM81.5 275.4a.9 .9 0 0 1 1-.3 .9 .9 0 0 1 .6 .8v1.4a.88 .88 0 0 1-.9 .9 .88 .88 0 0 1-.8-.9v-1.4zM85.1 279.3v-3.8v3.8M85.1 275.5l.2-.2h1.4l.2 .2v3.8h8.1M85.5 268.5a1.13 1.13 0 0 1 1.2-.1 1.13 1.13 0 0 1 .6 1v1.1a1.11 1.11 0 0 1-1.2 1.1 1.11 1.11 0 0 1-1.1-1.1l.1-1.5z"/>
<path d="M95 279.3v-3.8v3.8M95 275.5l.2-.2h1.4l.2 .2v3.8h74.5M95.1 268.5a1.13 1.13 0 0 1 1.1-.1 1.13 1.13 0 0 1 .6 1v1.1a1.11 1.11 0 0 1-1.1 1.1 1.11 1.11 0 0 1-1.1-1.1l.1-1.5zM96.8 263.7h1.7v1.9h-1.7zM96.8 260.5h1.7v1.9h-1.7zM98.6 275a1.48 1.48 0 0 1 1.6-.3 1.48 1.48 0 0 1 .9 1.4 2.11 2.11 0 0 1-.7 2.3 1.48 1.48 0 0 1-2.2-1.3v-1.4zM98.9 275.4a.9 .9 0 0 1 1-.3 .9 .9 0 0 1 .6 .8v1.4a.88 .88 0 0 1-.9 .9 .88 .88 0 0 1-.8-.9v-1.4zM101.1 271.3h2.3M101.1 271.2h2.3M101.1 271.1h2.3M101.1 271h2.3M101.1 270.9h2.3"/>
<path d="M101.1 270.8h2.3M101.1 270.7l2.3 .1v.5h-2.3v-2.2h.5v1.7M101.1 270.7h.5M101.1 270.6h.5M101.1 270.5h.5M101.1 270.4h.5M101.1 270.3h.5M101.1 270.2h.5M101.1 270.1h.5M101.1 270h.5M101.1 269.9h.5M101.1 269.8h.5"/>
<path d="M101.1 269.7h.5M101.1 269.6h.5M101.1 269.5h.5M101.1 269.4h.5M101.1 269.3h.5M101.1 269.2h.5M101.1 269.1h.5M101.6 264.4h8.5v6.4h-8.5zM103.3 266.1h2.3v1.1h-2.3zM103.3 267.9h2.3v1.1h-2.3zM103.9 271.8h1.2v1.1h-1.2zM106.1 271.8h1.2v1.1h-1.2z"/>
<path d="M106.2 266.1h2.2v1.1h-2.2zM106.2 267.9h2.2v1.1h-2.2zM109.4 267.5h.3v.2h-.3zM140.4 265.3h.2v.2h-.2zM140.4 268.5h.2v.2h-.2zM145.1 271.3h2.4M145.1 271.2h2.4M145.1 271.1h2.4M145.1 271h2.4M145.1 270.9h2.4M145.1 270.8h2.4M145.1 270.7l2.4 .1v.5h-2.4v-2.2h.6v1.7"/>
<path d="M145.1 270.7h.6M145.1 270.6h.6M145.1 270.5h.6M145.1 270.4h.6M145.1 270.3h.6M145.1 270.2h.6M145.1 270.1h.6M145.1 270h.6M145.1 269.9h.6M145.1 269.8h.6M145.1 269.7h.6M145.1 269.6h.6"/>
<path d="M145.1 269.5h.6M145.1 269.4h.6M145.1 269.3h.6M145.1 269.2h.6M145.1 269.1h.6M145.7 264.4h8.5v6.4h-8.5zM147.4 266.1h2.2v1.1h-2.2zM147.4 267.9h2.2v1.1h-2.2zM150.2 266.1h2.3v1.1h-2.3zM150.2 267.9h2.3v1.1h-2.3zM153.5 267.5h.2v.2h-.2zM171.3 279.3v-34.6v34.6"/>
<circle cx="54.2" cy="21.6" r="3.1"/>
<circle cx="54.2" cy="21.6" r="5.8"/>
<circle cx="59.2" cy="30.7" r="1.05"/>
<circle cx="106.5" cy="23" r="1.03"/>
<circle cx="115.7" cy="23" r="1.03"/>
<circle cx="159.4" cy="31.5" r="1.05"/>
<circle cx="162.5" cy="21.6" r="3.1"/>
<circle cx="162.5" cy="21.6" r="5.8"/>
<circle cx="55.8" cy="65.1" r="2.09"/>
<circle cx="70.5" cy="65.1" r="2.09"/>
<circle cx="111.5" cy="96" r="1.05"/>
<circle cx="116.8" cy="96" r="1.6"/>
<circle cx="116.8" cy="96" r="1.05"/>
<circle cx="122.1" cy="96" r="1.6"/>
<circle cx="122.1" cy="96" r="1.05"/>
<circle cx="111.4" cy="101.3" r="1.6"/>
<circle cx="111.5" cy="101.3" r="1.05"/>
<circle cx="116.8" cy="101.3" r="1.6"/>
<circle cx="116.8" cy="101.3" r="1.05"/>
<circle cx="64.8" cy="197.9" r=".73"/>
<circle cx="64.8" cy="213.7" r=".73"/>
<circle cx="61.4" cy="234" r="1.24"/>
<circle cx="61.4" cy="244.7" r="1.24"/>
<circle cx="159.9" cy="259.8" r="1.05"/>
<circle cx="54.2" cy="270.5" r="3.1"/>
<circle cx="54.2" cy="270.5" r="5.8"/>
<circle cx="86.1" cy="269.9" r=".83"/>
<circle cx="95.7" cy="269.9" r=".83"/>
<circle cx="162.5" cy="270.5" r="3.1"/>
<circle cx="162.5" cy="270.5" r="5.8"/>
</g>
<path d="M45.9 33.8h125.4v224.4h-125.4zM90.1 259.6h2.4v7.4h-2.4z" fill="none" stroke="#000" stroke-width=".32"/>
<g fill="none" stroke="#000" stroke-width=".25">
<path d="M61.5 16h6.1v2.7h-6.1zM80.3 15.7h2.7v6h-2.7zM90.1 15.7h2.7v6h-2.7zM100 15.7h2.7v6h-2.7zM109.9 15.7h2.6v6h-2.6zM63.8 24h5.3M63.8 26.7h5.3M71.5 24h-1.6v2.2h1.6M72.6 24h1.6v2.2h-1.6M80.3 23v5.3M83 23v5.3M90.1 23v5.3"/>
<path d="M92.8 23v5.3M100 23v5.3M102.7 23v5.3M109.9 23v5.3M112.5 23v5.3M96.3 260h2.7v6.1h-2.7zM105.1 271.3h-1.6v2.1h1.6M106.1 271.3h1.6v2.1h-1.6M139.2 264h2.6v6.1h-2.6z"/>
</g>
<path d="M63.8 24a2.65 2.65 0 0 0 0 2.7M69.1 24a2.45 2.45 0 0 1 0 2.6M80.3 28.3a2.45 2.45 0 0 0 2.6 0M80.3 23a2.57 2.57 0 0 1 2.6 0M90.1 28.3a2.45 2.45 0 0 0 2.7 0M90.1 23a2.57 2.57 0 0 1 2.7 0M100 28.3a2.45 2.45 0 0 0 2.6 0M100 23a2.57 2.57 0 0 1 2.6 0M109.9 28.3a2.45 2.45 0 0 0 2.6 0M109.9 23a2.57 2.57 0 0 1 2.6 0" fill="none" stroke="#000" stroke-width=".28"/>
<path d="M80.6 22.2h2.1M90.4 22.2h2.1M100.3 22.2h2.1M110.1 22.2h2.2M96.5 266.5h2.2" fill="none" stroke="#000" stroke-width=".63"/>
<path d="M86.2 116.8h56.2v20h-56.2zM69.4 149.3h2.9v2.9h-2.9zM69.4 153.5h2.9v3h-2.9z" fill="none" stroke="#000" stroke-width=".53"/>
<use href="#words"/>
</svg>
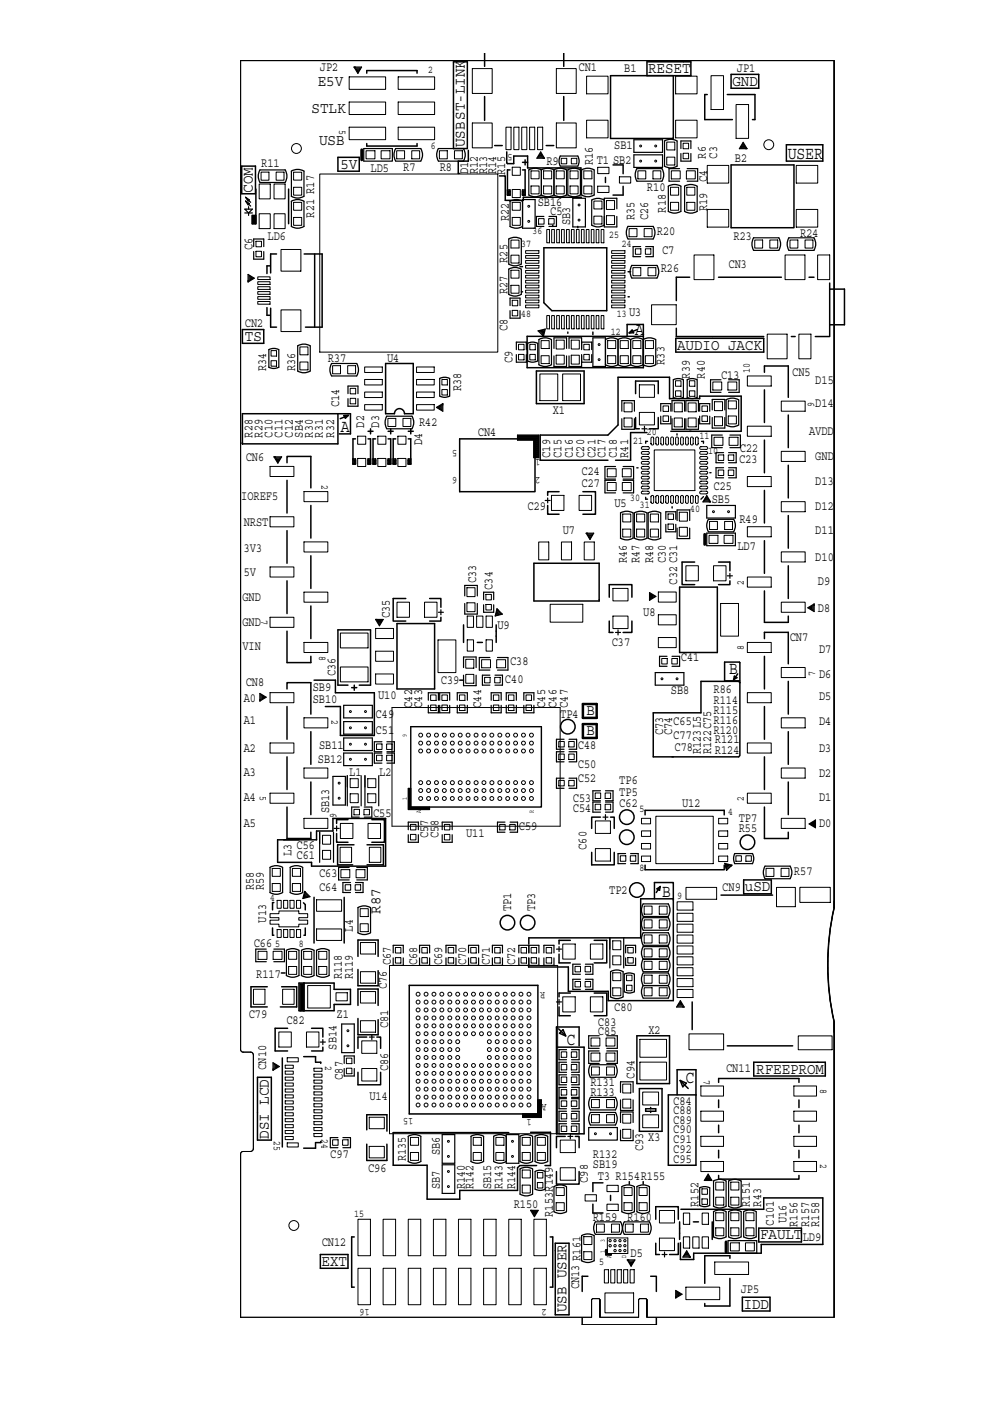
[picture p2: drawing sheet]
<svg xmlns="http://www.w3.org/2000/svg" width="210mm" height="297mm" viewBox="0 0 210 297" stroke-linecap="round" stroke-linejoin="round" font-family="sans-serif">
<defs><g id="words">
<g font-size="3.8">
<text x="167.1" y="33.6">USER</text>
<text x="134.7" y="71.1">A</text>
<text x="72.3" y="91.5">A</text>
<text x="154.6" y="143">B</text>
<text x="140.4" y="190.1">B</text>
<text x="120.2" y="221.5">C</text>
<text x="145.4" y="229.6">C</text>
</g>
<g font-size="3.3">
<text x="137.5" y="15.5">RESET</text>
<text x="67.4" y="18.2">E5V</text>
<text x="155.3" y="18.2">GND</text>
<text x="66.1" y="24">STLK</text>
<text x="67.7" y="30.7">USB</text>
<text x="72.2" y="35.8">5V</text>
<text x="98.6" y="31.2" transform="rotate(-90 98.6 31.2)">USBST-LINK</text>
<text x="53.7" y="40.8" transform="rotate(-90 53.7 40.8)">COM</text>
<text x="51.9" y="72.3">TS</text>
<text x="143.6" y="74.1">AUDIO JACK</text>
<text x="124.4" y="155.9">B</text>
<text x="124.4" y="151.7">B</text>
<text x="158" y="189">uSD</text>
<text x="80.7" y="193.8" transform="rotate(-90 80.7 193.8)">R87</text>
<text x="160.4" y="227.6">RFEEPROM</text>
<text x="57" y="241.5" transform="rotate(-90 57 241.5)">DSI LCD</text>
<text x="161.2" y="262.8">FAULT</text>
<text x="68.2" y="268.4">EXT</text>
<text x="120.2" y="278.2" transform="rotate(-90 120.2 278.2)">USB USER</text>
<text x="157.7" y="277.4">IDD</text>
</g>
<g font-size="2.8">
<text x="67.8" y="15">JP2</text>
<text x="122.7" y="15">CN1</text>
<text x="132.4" y="15.2">B1</text>
<text x="156.3" y="15.2">JP1</text>
<text x="55.4" y="35.5">R11</text>
<text x="115.9" y="35">R9</text>
<text x="125.8" y="35" transform="rotate(-90 125.8 35)">R16</text>
<text x="126.6" y="34.7">T1 SB2</text>
<text x="130.3" y="31.5">SB1</text>
<text x="149.7" y="33.6" transform="rotate(-90 149.7 33.6)">R6</text>
<text x="152.1" y="33.6" transform="rotate(-90 152.1 33.6)">C3</text>
<text x="155.9" y="34.4">B2</text>
<text x="78.6" y="36.6">LD5</text>
<text x="85.5" y="36.3">R7</text>
<text x="93.3" y="36.3">R8</text>
<text x="99.3" y="36.8" transform="rotate(-90 99.3 36.8)">D1</text>
<text x="101.3" y="36.9" transform="rotate(-90 101.3 36.9)">R12</text>
<text x="103.3" y="36.9" transform="rotate(-90 103.3 36.9)">R13</text>
<text x="105.2" y="37" transform="rotate(-90 105.2 37)">R14</text>
<text x="107.2" y="37" transform="rotate(-90 107.2 37)">R15</text>
<text x="137.2" y="40.6">R10</text>
<text x="150" y="38.7" transform="rotate(-90 150 38.7)">C4</text>
<text x="66.6" y="46.1" transform="rotate(-90 66.6 46.1)">R21 R17</text>
<text x="107.9" y="46.9" transform="rotate(-90 107.9 46.9)">R22</text>
<text x="114" y="43.8">SB16</text>
<text x="116.7" y="45.6">C5</text>
<text x="121" y="47.8" transform="rotate(-90 121 47.8)">SB3</text>
<text x="134.6" y="46.7" transform="rotate(-90 134.6 46.7)">R35</text>
<text x="137.5" y="46.7" transform="rotate(-90 137.5 46.7)">C26</text>
<text x="141.2" y="45.1" transform="rotate(-90 141.2 45.1)">R18</text>
<text x="150" y="44.8" transform="rotate(-90 150 44.8)">R19</text>
<text x="53.6" y="53.1" transform="rotate(-90 53.6 53.1)">C6</text>
<text x="56.7" y="50.9">LD6</text>
<text x="139.3" y="49.9">R20</text>
<text x="140.4" y="53.9">C7</text>
<text x="155.6" y="50.9">R23</text>
<text x="169.7" y="50.1">R24</text>
<text x="107.6" y="55.7" transform="rotate(-90 107.6 55.7)">R25</text>
<text x="140.1" y="57.6">R26</text>
<text x="154.5" y="56.8">CN3</text>
<text x="107.6" y="62.4" transform="rotate(-90 107.6 62.4)">R27</text>
<text x="51.9" y="69.3">CN2</text>
<text x="107.6" y="70.1" transform="rotate(-90 107.6 70.1)">C8</text>
<text x="133.4" y="66.9">U3</text>
<text x="69.5" y="76.8">R37</text>
<text x="82.1" y="76.8">U4</text>
<text x="108.7" y="77.1" transform="rotate(-90 108.7 77.1)">C9</text>
<text x="140.9" y="77.3" transform="rotate(-90 140.9 77.3)">R33</text>
<text x="56.5" y="78.7" transform="rotate(-90 56.5 78.7)">R34</text>
<text x="62.6" y="78.7" transform="rotate(-90 62.6 78.7)">R36</text>
<text x="97.8" y="82.9" transform="rotate(-90 97.8 82.9)">R38</text>
<text x="146.3" y="80.3" transform="rotate(-90 146.3 80.3)">R39</text>
<text x="149.5" y="80.3" transform="rotate(-90 149.5 80.3)">R40</text>
<text x="152.9" y="80.3">C13</text>
<text x="168" y="79.7">CN5</text>
<text x="172.9" y="81.3">D15</text>
<text x="71.9" y="86.4" transform="rotate(-90 71.9 86.4)">C14</text>
<text x="117.2" y="87.8">X1</text>
<text x="172.9" y="86.4">D14</text>
<text x="53.6" y="92.8" transform="rotate(-90 53.6 92.8)">R28</text>
<text x="55.7" y="92.8" transform="rotate(-90 55.7 92.8)">R29</text>
<text x="57.8" y="92.8" transform="rotate(-90 57.8 92.8)">C10</text>
<text x="59.9" y="92.8" transform="rotate(-90 59.9 92.8)">C11</text>
<text x="62.1" y="92.8" transform="rotate(-90 62.1 92.8)">C12</text>
<text x="64.2" y="92.8" transform="rotate(-90 64.2 92.8)">SB4</text>
<text x="66.3" y="92.8" transform="rotate(-90 66.3 92.8)">R30</text>
<text x="68.5" y="92.8" transform="rotate(-90 68.5 92.8)">R31</text>
<text x="70.9" y="92.8" transform="rotate(-90 70.9 92.8)">R32</text>
<text x="77.3" y="90.7" transform="rotate(-90 77.3 90.7)">D2</text>
<text x="80.5" y="90.7" transform="rotate(-90 80.5 90.7)">D3</text>
<text x="88.9" y="90.3">R42</text>
<text x="89.5" y="94.4" transform="rotate(-90 89.5 94.4)">D4</text>
<text x="101.3" y="92.4">CN4</text>
<text x="156.9" y="95.8">C22</text>
<text x="171.6" y="92.2">AVDD</text>
<text x="52.1" y="97.8">CN6</text>
<text x="116.7" y="97" transform="rotate(-90 116.7 97)">C19</text>
<text x="119.1" y="97" transform="rotate(-90 119.1 97)">C15</text>
<text x="121.5" y="97" transform="rotate(-90 121.5 97)">C16</text>
<text x="123.4" y="100.8">C24</text>
<text x="123.9" y="97" transform="rotate(-90 123.9 97)">C20</text>
<text x="126.3" y="97" transform="rotate(-90 126.3 97)">C21</text>
<text x="128.4" y="97" transform="rotate(-90 128.4 97)">C17</text>
<text x="130.8" y="97" transform="rotate(-90 130.8 97)">C18</text>
<text x="133.2" y="97" transform="rotate(-90 133.2 97)">R41</text>
<text x="156.8" y="98.1">C23</text>
<text x="172.9" y="97.6">GND</text>
<text x="51.2" y="106.1">IOREF5</text>
<text x="123.4" y="103.2">C27</text>
<text x="130.3" y="107.4">U5</text>
<text x="151" y="106.7">SB5</text>
<text x="151.3" y="103.8">C25</text>
<text x="172.9" y="102.9">D13</text>
<text x="51.7" y="111.4">NRST</text>
<text x="111.9" y="108.2">C29</text>
<text x="119.4" y="113.3">U7</text>
<text x="156.8" y="110.8">R49</text>
<text x="172.9" y="113.3">D11</text>
<text x="172.9" y="108.2">D12</text>
<text x="51.7" y="117">3V3</text>
<text x="132.9" y="119.4" transform="rotate(-90 132.9 119.4)">R46</text>
<text x="135.6" y="119.4" transform="rotate(-90 135.6 119.4)">R47</text>
<text x="138.6" y="119.4" transform="rotate(-90 138.6 119.4)">R48</text>
<text x="141.2" y="119.4" transform="rotate(-90 141.2 119.4)">C30</text>
<text x="156.4" y="116.7">LD7</text>
<text x="172.9" y="118.9">D10</text>
<text x="51.7" y="122.1">5V</text>
<text x="101" y="123.7" transform="rotate(-90 101 123.7)">C33</text>
<text x="104.4" y="125" transform="rotate(-90 104.4 125)">C34</text>
<text x="143.6" y="124" transform="rotate(-90 143.6 124)">C32 C31</text>
<text x="173.5" y="124">D9</text>
<text x="51.4" y="127.4">GND</text>
<text x="82.7" y="131.1" transform="rotate(-90 82.7 131.1)">C35</text>
<text x="136.4" y="130.6">U8</text>
<text x="173.5" y="129.8">D8</text>
<text x="51.4" y="132.8">GND</text>
<text x="51.4" y="137.8">VIN</text>
<text x="105.5" y="133.3">U9</text>
<text x="129.8" y="137">C37</text>
<text x="167.5" y="136">CN7</text>
<text x="71.1" y="143.4" transform="rotate(-90 71.1 143.4)">C36</text>
<text x="108.2" y="141">C38</text>
<text x="144.4" y="140.2">C41</text>
<text x="173.7" y="143.7">D6</text>
<text x="173.7" y="138.3">D7</text>
<text x="51.7" y="148.7">A0</text>
<text x="52.1" y="145.5">CN8</text>
<text x="66.3" y="149">SB10</text>
<text x="66.3" y="146.6">SB9</text>
<text x="80.2" y="148.2">U10</text>
<text x="93.5" y="145">C39</text>
<text x="107.1" y="144.7">C40</text>
<text x="142.3" y="147.1">SB8</text>
<text x="151.3" y="149.3">R114</text>
<text x="151.3" y="146.9">R86</text>
<text x="173.7" y="148.5">D5</text>
<text x="51.7" y="153.5">A1</text>
<text x="79.7" y="152.2">C49</text>
<text x="79.7" y="155.7">C51</text>
<text x="87.4" y="150.1" transform="rotate(-90 87.4 150.1)">C42</text>
<text x="89.5" y="150.1" transform="rotate(-90 89.5 150.1)">C43</text>
<text x="102" y="150.1" transform="rotate(-90 102 150.1)">C44</text>
<text x="115.6" y="150.1" transform="rotate(-90 115.6 150.1)">C45</text>
<text x="118" y="150.1" transform="rotate(-90 118 150.1)">C46</text>
<text x="118.8" y="152.2">TP4</text>
<text x="120.4" y="150.1" transform="rotate(-90 120.4 150.1)">C47</text>
<text x="140.7" y="155.9" transform="rotate(-90 140.7 155.9)">C73</text>
<text x="142.5" y="155.9" transform="rotate(-90 142.5 155.9)">C74</text>
<text x="142.8" y="153.8">C65</text>
<text x="151.3" y="153.5">R116</text>
<text x="151.3" y="155.7">R120</text>
<text x="151.3" y="151.4">R115</text>
<text x="173.7" y="153.8">D4</text>
<text x="51.7" y="159.4">A2</text>
<text x="67.4" y="161.8">SB12</text>
<text x="67.7" y="158.9">SB11</text>
<text x="122.6" y="158.9">C48</text>
<text x="142.8" y="156.7">C77</text>
<text x="143.1" y="159.1">C78</text>
<text x="148.7" y="159.9" transform="rotate(-90 148.7 159.9)">R123L5</text>
<text x="150.8" y="159.9" transform="rotate(-90 150.8 159.9)">R122C75</text>
<text x="151.6" y="159.9">R124</text>
<text x="151.6" y="157.5">R121</text>
<text x="173.7" y="159.4">D3</text>
<text x="51.7" y="164.5">A3</text>
<text x="74.1" y="164.5">L1</text>
<text x="80.5" y="164.5">L2</text>
<text x="122.6" y="165.8">C52</text>
<text x="122.6" y="162.9">C50</text>
<text x="131.4" y="166.3">TP6</text>
<text x="173.7" y="164.7">D2</text>
<text x="51.7" y="169.8">A4</text>
<text x="69.8" y="172.4" transform="rotate(-90 69.8 172.4)">SB13</text>
<text x="79.1" y="173.2">C55</text>
<text x="121.5" y="170.1">C53</text>
<text x="121.5" y="172.2">C54</text>
<text x="131.4" y="171.1">C62</text>
<text x="131.4" y="168.7">TP5</text>
<text x="144.7" y="171.1">U12</text>
<text x="173.7" y="169.8">D1</text>
<text x="51.7" y="175.4">A5</text>
<text x="62.9" y="179.9">C56</text>
<text x="90.8" y="177.8" transform="rotate(-90 90.8 177.8)">C57</text>
<text x="93" y="177.8" transform="rotate(-90 93 177.8)">C58</text>
<text x="98.8" y="177.5">U11</text>
<text x="110" y="175.9">C59</text>
<text x="156.7" y="176.4">R55</text>
<text x="156.7" y="174.3">TP7</text>
<text x="173.7" y="175.4">D0</text>
<text x="61.8" y="181.5" transform="rotate(-90 61.8 181.5)">L3</text>
<text x="62.9" y="182">C61</text>
<text x="124.4" y="180.2" transform="rotate(-90 124.4 180.2)">C60</text>
<text x="168.4" y="185.5">R57</text>
<text x="53.8" y="188.7" transform="rotate(-90 53.8 188.7)">R58</text>
<text x="55.9" y="188.7" transform="rotate(-90 55.9 188.7)">R59</text>
<text x="67.7" y="186">C63</text>
<text x="67.7" y="189">C64</text>
<text x="129.2" y="189.5">TP2</text>
<text x="153.2" y="189">CN9</text>
<text x="56.5" y="195.6" transform="rotate(-90 56.5 195.6)">U13</text>
<text x="74.9" y="197.5" transform="rotate(-90 74.9 197.5)">L4</text>
<text x="108.4" y="193.2" transform="rotate(-90 108.4 193.2)">TP1</text>
<text x="113.5" y="193.2" transform="rotate(-90 113.5 193.2)">TP3</text>
<text x="53.8" y="200.7">C66</text>
<text x="54.4" y="207.3">R117</text>
<text x="72.5" y="207.6" transform="rotate(-90 72.5 207.6)">R118</text>
<text x="74.9" y="207.6" transform="rotate(-90 74.9 207.6)">R119</text>
<text x="82.1" y="209.8" transform="rotate(-90 82.1 209.8)">C76</text>
<text x="82.9" y="204.7" transform="rotate(-90 82.9 204.7)">C67</text>
<text x="88.5" y="204.7" transform="rotate(-90 88.5 204.7)">C68</text>
<text x="93.8" y="204.7" transform="rotate(-90 93.8 204.7)">C69</text>
<text x="98.8" y="204.7" transform="rotate(-90 98.8 204.7)">C70</text>
<text x="103.9" y="204.7" transform="rotate(-90 103.9 204.7)">C71</text>
<text x="109.2" y="204.7" transform="rotate(-90 109.2 204.7)">C72</text>
<text x="52.7" y="215.9">C79</text>
<text x="71.4" y="215.9">Z1</text>
<text x="130.3" y="214.3">C80</text>
<text x="60.7" y="217.2">C82</text>
<text x="82.3" y="218" transform="rotate(-90 82.3 218)">C81</text>
<text x="126.8" y="217.5">C83</text>
<text x="126.8" y="219.4">C85</text>
<text x="137.5" y="219.1">X2</text>
<text x="56.5" y="226.8" transform="rotate(-90 56.5 226.8)">CN10</text>
<text x="71.4" y="222.5" transform="rotate(-90 71.4 222.5)">SB14</text>
<text x="82.3" y="227.1" transform="rotate(-90 82.3 227.1)">C86</text>
<text x="154" y="227.4">CN11</text>
<text x="72.7" y="228.9" transform="rotate(-90 72.7 228.9)">C87</text>
<text x="78.3" y="233.2">U14</text>
<text x="125.2" y="232.4">R133</text>
<text x="125.2" y="230.3">R131</text>
<text x="134.6" y="228.7" transform="rotate(-90 134.6 228.7)">C94</text>
<text x="142.8" y="236.1">C88</text>
<text x="142.8" y="238.3">C89</text>
<text x="142.8" y="234.3">C84</text>
<text x="70.1" y="245.5">C97</text>
<text x="93.3" y="244.9" transform="rotate(-90 93.3 244.9)">SB6</text>
<text x="125.8" y="245.5">R132</text>
<text x="136.4" y="244.1" transform="rotate(-90 136.4 244.1)">C93</text>
<text x="137.5" y="242">X3</text>
<text x="142.8" y="240.1">C90</text>
<text x="142.8" y="242.3">C91</text>
<text x="142.8" y="244.4">C92</text>
<text x="78.1" y="248.4">C96</text>
<text x="86.1" y="246.3" transform="rotate(-90 86.1 246.3)">R135</text>
<text x="124.7" y="250.8" transform="rotate(-90 124.7 250.8)">C98</text>
<text x="125.8" y="247.6">SB19</text>
<text x="126.8" y="250.3">T3 R154R155</text>
<text x="142.8" y="246.5">C95</text>
<text x="93.3" y="252.1" transform="rotate(-90 93.3 252.1)">SB7</text>
<text x="98.6" y="252.1" transform="rotate(-90 98.6 252.1)">R140</text>
<text x="100.4" y="252.1" transform="rotate(-90 100.4 252.1)">R142</text>
<text x="104.2" y="252.1" transform="rotate(-90 104.2 252.1)">SB15</text>
<text x="106.6" y="252.1" transform="rotate(-90 106.6 252.1)">R143</text>
<text x="109" y="256.1">R150</text>
<text x="109.2" y="252.1" transform="rotate(-90 109.2 252.1)">R144</text>
<text x="117.2" y="258" transform="rotate(-90 117.2 258)">R153R149</text>
<text x="148.1" y="255.8" transform="rotate(-90 148.1 255.8)">R152</text>
<text x="159.1" y="255.8" transform="rotate(-90 159.1 255.8)">R151</text>
<text x="161.5" y="255.8" transform="rotate(-90 161.5 255.8)">R43</text>
<text x="125.7" y="258.8">R159</text>
<text x="133.1" y="258.8">R160</text>
<text x="164.1" y="259.8" transform="rotate(-90 164.1 259.8)">C101</text>
<text x="166.8" y="259.3" transform="rotate(-90 166.8 259.3)">U16</text>
<text x="169.2" y="260.1" transform="rotate(-90 169.2 260.1)">R156</text>
<text x="170.3" y="263">LD9</text>
<text x="171.6" y="260.1" transform="rotate(-90 171.6 260.1)">R157</text>
<text x="173.7" y="260.1" transform="rotate(-90 173.7 260.1)">R158</text>
<text x="68.2" y="264.1">CN12</text>
<text x="133.8" y="266.5">D5</text>
<text x="122.8" y="273.4" transform="rotate(-90 122.8 273.4)">CN13 R161</text>
<text x="157.1" y="274.2">JP5</text>
</g>
<g font-size="2.3">
<text x="90.8" y="15.5">2</text>
<text x="71.9" y="27.5" transform="rotate(90 71.9 27.5)">5</text>
<text x="91.4" y="31.5">6</text>
<text x="108.7" y="32.6" transform="rotate(-180 108.7 32.6)">5</text>
<text x="110.6" y="52.3">37</text>
<text x="113" y="49.6">36</text>
<text x="129.2" y="50.4">25</text>
<text x="131.9" y="52.3">24</text>
<text x="110.6" y="67.2">48</text>
<text x="129.5" y="70.9">12</text>
<text x="130.8" y="67.1">13</text>
<text x="159.1" y="79.2" transform="rotate(-90 159.1 79.2)">10</text>
<text x="172.7" y="86.4" transform="rotate(-90 172.7 86.4)">9</text>
<text x="97" y="95.4" transform="rotate(-180 97 95.4)">5</text>
<text x="134.3" y="94.1">21</text>
<text x="137.2" y="92.2">20</text>
<text x="148.4" y="93">11</text>
<text x="97" y="101" transform="rotate(-180 97 101)">6</text>
<text x="114.6" y="101" transform="rotate(-180 114.6 101)">2</text>
<text x="114.6" y="97.3" transform="rotate(-180 114.6 97.3)">1</text>
<text x="150.2" y="96.3">10</text>
<text x="68.2" y="102.9" transform="rotate(90 68.2 102.9)">2</text>
<text x="133.7" y="106.3">30</text>
<text x="135.7" y="107.8">31</text>
<text x="146.4" y="108.6">40</text>
<text x="157.7" y="124" transform="rotate(-90 157.7 124)">2</text>
<text x="55.4" y="131.4" transform="rotate(90 55.4 131.4)">7</text>
<text x="157.7" y="137.8" transform="rotate(-90 157.7 137.8)">8</text>
<text x="67.7" y="139.1" transform="rotate(90 67.7 139.1)">8</text>
<text x="172.9" y="143.4" transform="rotate(-90 172.9 143.4)">7</text>
<text x="70.3" y="152.7" transform="rotate(90 70.3 152.7)">2</text>
<text x="55.1" y="168.7" transform="rotate(90 55.1 168.7)">5</text>
<text x="70.1" y="172.4" transform="rotate(90 70.1 172.4)">6</text>
<text x="135.6" y="172.2">5</text>
<text x="154.4" y="172.8">4</text>
<text x="157.7" y="169.8" transform="rotate(-90 157.7 169.8)">2</text>
<text x="135.6" y="184.7">8</text>
<text x="57.3" y="191.1">4</text>
<text x="143.6" y="190.5">9</text>
<text x="58.4" y="200.7">5</text>
<text x="63.4" y="200.7">8</text>
<text x="115.6" y="210.3" transform="rotate(-180 115.6 210.3)">R</text>
<text x="69" y="226" transform="rotate(90 69 226)">2</text>
<text x="115.9" y="234" transform="rotate(-180 115.9 234)">A</text>
<text x="149.2" y="228.9" transform="rotate(90 149.2 228.9)">7</text>
<text x="174" y="230.8" transform="rotate(90 174 230.8)">8</text>
<text x="87.7" y="236.9" transform="rotate(-180 87.7 236.9)">15</text>
<text x="112.7" y="237.2" transform="rotate(-180 112.7 237.2)">1</text>
<text x="58.1" y="242" transform="rotate(90 58.1 242)">25</text>
<text x="68.2" y="241.5" transform="rotate(90 68.2 241.5)">24</text>
<text x="174" y="246.8" transform="rotate(90 174 246.8)">2</text>
<text x="75.1" y="258">15</text>
<text x="127.1" y="268.1">5</text>
<text x="78.3" y="277.4" transform="rotate(-180 78.3 277.4)">16</text>
<text x="115.9" y="277.4" transform="rotate(-180 115.9 277.4)">2</text>
</g>
<g font-size="1.5">
<text x="86.3" y="156.2" transform="rotate(-90 86.3 156.2)">9</text>
<text x="86.3" y="169.5" transform="rotate(-90 86.3 169.5)">1</text>
<text x="89.3" y="172.4" transform="rotate(-90 89.3 172.4)">A</text>
<text x="113.2" y="172.4" transform="rotate(-90 113.2 172.4)">R</text>
<text x="128.3" y="263.3" transform="rotate(-90 128.3 263.3)">3</text>
<text x="128.3" y="265.7" transform="rotate(-90 128.3 265.7)">1</text>
<text x="129.6" y="266.8" transform="rotate(-90 129.6 266.8)">A</text>
<text x="132.8" y="266.8" transform="rotate(-90 132.8 266.8)">D</text>
</g>
</g></defs>
<g fill="none" stroke="#000" stroke-width=".21">
<path d="M51 12.8v209.7l.3 .5 .3 .1h1.9l.2 .5M51 12.8h125.9h-125.9M74.1 16.3h7.7v2.6h-7.7zM84.5 16.3h7.7v2.6h-7.7zM100.2 14.5h4.2v5.3h-4.2zM118 14.5h4.2v5.3h-4.2zM124.4 16.2h4.6v3.7h-4.6zM143.3 16.2h4.5v3.7h-4.5zM150.8 16h2.7v7.2h-2.7zM176.9 12.8v179.6v-179.6M55 39h2.3v3.2h-2.3zM55.4 36.5h1.6v1.7h-1.6z"/>
<path d="M58.1 39h2.4v3.2h-2.4zM58.6 36.5h1.6v1.7h-1.6zM62.3 39.7h1.7v1.7h-1.7zM62.3 36.5h1.7v1.7h-1.7zM67.8 36.9h37.8v37.8h-37.8zM74.1 27h7.7v2.6h-7.7zM74.1 21.6h7.7v2.7h-7.7zM77.6 32h1.9v1.7h-1.9zM80.8 32h1.9v1.7h-1.9zM84.1 32h1.7v1.7h-1.7zM84.5 27h7.7v2.6h-7.7zM84.5 21.6h7.7v2.7h-7.7z"/>
<path d="M87.3 32h1.7v1.7h-1.7zM93.2 32h1.7v1.7h-1.7zM96.4 32h1.7v1.7h-1.7zM100.2 26.1h4.2v5.2h-4.2zM107.3 27h1.1v4.7h-1.1zM108.6 35.5h1.8v1.7h-1.8zM109 27h1.1v4.7h-1.1zM110.7 27h1v4.7h-1zM112.3 27h1.1v4.7h-1.1zM112.6 39.4h1.7v1.7h-1.7zM112.6 36.2h1.7v1.7h-1.7zM114 27h1.1v4.7h-1.1z"/>
<path d="M115.3 39.4h1.7v1.7h-1.7zM115.3 36.2h1.7v1.7h-1.7zM118 39.4h1.7v1.7h-1.7zM118 36.2h1.7v1.7h-1.7zM118 26.1h4.2v5.2h-4.2zM119 33.6h1.2v1.1h-1.2zM120.9 39.4h1.7v1.7h-1.7zM120.9 36.2h1.7v1.7h-1.7zM121.2 33.6h1.1v1.1h-1.1zM123.8 36.2h1.7v1.7h-1.7zM123.8 39.4h1.7v1.7h-1.7zM124.4 25.5h4.6v3.7h-4.6z"/>
<path d="M126.8 39.5h2.4v1.3h-2.4zM126.8 35.5h2.4v1.3h-2.4zM131.4 37.5h2.4v1.3h-2.4zM135.3 36.2h1.7v1.7h-1.7zM138.5 36.2h1.7v1.7h-1.7zM141.4 30.1h1.7v1.7h-1.7zM141.4 33.3h1.7v1.7h-1.7zM142.2 39.7h1.7v1.7h-1.7zM142.4 36.2h1.9v1.7h-1.9zM143.3 25.5h4.5v3.7h-4.5zM144.9 32.5h1.2v1.2h-1.2zM144.9 30.4h1.2v1.1h-1.2z"/>
<path d="M145.6 36.2h1.9v1.7h-1.9zM145.7 39.7h1.7v1.7h-1.7zM150 35.1h4.6v3.7h-4.6zM156.1 22.2h2.7v7.1h-2.7zM168.9 35.1h4.5v3.7h-4.5zM53.5 45.6h.8v1.9h-.8zM53.5 47.4h.8M53.5 47.3h.8M53.5 47.2h.8M53.5 47.1h.8M53.5 47h.8M53.5 46.9h.8"/>
<path d="M53.5 46.8h.8M53.5 46.7h.8M53.5 46.6h.8M53.5 46.5h.8M53.5 46.4h.8M53.5 46.3h.8M53.5 46.2h.8M53.5 46.1h.8M53.5 46h.8M53.5 45.9h.8M53.5 45.8h.8M53.5 45.7h.8"/>
<path d="M54.3 53.3h1.2v1.1h-1.2zM54.3 51.2h1.2v1.1h-1.2zM54.7 58.7h2.6v.6h-2.6zM54.7 59.7h2.6v.6h-2.6zM55 45.3h2.3v3.2h-2.3zM58.1 45.3h2.4v3.2h-2.4zM59.6 52.9h4.2v4.6h-4.2zM62.3 46.1h1.7v1.7h-1.7zM62.3 42.9h1.7v1.7h-1.7zM108.4 50.9h1.7v1.7h-1.7zM108.4 54.1h1.7v1.7h-1.7zM108.4 57.3h1.7v1.7h-1.7z"/>
<path d="M108.6 46.1h1.8v1.7h-1.8zM108.6 42.9h1.8v1.7h-1.8zM108.6 40.2h1.8v1.7h-1.8zM111.5 55.2h2.8v.6h-2.8zM111.5 54.2h2.8v.6h-2.8zM111.5 53.1h2.8v.6h-2.8zM111.5 59.4h2.8v.6h-2.8zM111.5 58.4h2.8v.5h-2.8zM111.5 57.3h2.8v.6h-2.8zM111.5 56.3h2.8v.6h-2.8zM114.2 46.4h1.2v1.1h-1.2zM116 48.7h.5v2.8h-.5z"/>
<path d="M116.4 46.4h1.1v1.1h-1.1zM117 48.7h.6v2.8h-.6zM118.1 48.7h.5v2.8h-.5zM119.1 48.7h.6v2.8h-.6zM120.2 48.7h.5v2.8h-.5zM121.2 48.7h.6v2.8h-.6zM122.3 48.7h.5v2.8h-.5zM123.3 48.7h.6v2.8h-.6zM124.4 48.7h.5v2.8h-.5zM125.4 48.7h.6v2.8h-.6zM126 42.6h1.7v1.7h-1.7zM126 45.8h1.7v1.7h-1.7z"/>
<path d="M126.4 48.7h.6v2.8h-.6zM127.5 48.7h.6v2.8h-.6zM128.6 45.7h1.7v1.9h-1.7zM128.6 42.5h1.7v1.9h-1.7zM129.7 53.1h2.8v.6h-2.8zM129.7 54.2h2.8v.6h-2.8zM129.7 55.2h2.8v.6h-2.8zM129.7 57.3h2.8v.6h-2.8zM129.7 58.4h2.8v.5h-2.8zM129.7 59.4h2.8v.6h-2.8zM129.7 56.3h2.8v.6h-2.8zM133.4 48.5h1.7v1.7h-1.7z"/>
<path d="M134.2 56.7h1.7v1.8h-1.7zM134.8 52.7h1.1v1.2h-1.1zM136.6 48.5h1.7v1.7h-1.7zM136.9 52.7h1.1v1.2h-1.1zM137.4 56.7h1.7v1.8h-1.7zM142.2 42.9h1.7v1.7h-1.7zM145.7 42.9h1.7v1.7h-1.7zM147.2 54.1h4.2v5.2h-4.2zM150 44.4h4.6v3.8h-4.6zM160.1 50.9h1.7v1.7h-1.7zM163.3 50.9h1.7v1.7h-1.7zM166.5 54.1h4.2v5.2h-4.2z"/>
<path d="M167.6 50.9h1.6v1.7h-1.6zM168.9 44.4h4.5v3.8h-4.5zM170.8 50.9h1.6v1.7h-1.6zM173.4 54.1h2.6v5.2h-2.6zM54.7 61.8h2.6v.6h-2.6zM54.7 62.9h2.6v.6h-2.6zM54.7 63.9h2.6v.6h-2.6zM54.7 60.8h2.6v.6h-2.6zM57.5 74.3h1.2v1.2h-1.2zM57.5 76.5h1.2v1.1h-1.2zM59.6 65.7h4.2v4.6h-4.2zM63.6 73.6h1.7v1.6h-1.7z"/>
<path d="M63.6 76.8h1.7v1.6h-1.7zM70.5 77.5h1.7v1.7h-1.7zM73.7 77.5h1.7v1.7h-1.7zM77.3 77.8h3.8v1.2h-3.8zM88.3 77.8h3.8v1.2h-3.8zM108.4 60.5h1.7v1.7h-1.7zM108.6 65.8h1.2v1.2h-1.2zM108.6 63.7h1.2v1.1h-1.2zM110 73h1.1v1.2h-1.1zM110 75.1h1.1v1.2h-1.1zM111.5 60.5h2.8v.5h-2.8zM111.5 64.7h2.8v.6h-2.8z"/>
<path d="M111.5 63.6h2.8v.6h-2.8zM111.5 62.6h2.8v.6h-2.8zM111.5 61.5h2.8v.6h-2.8zM112.4 73h1.1v1.2h-1.1zM112.4 75.1h1.1v1.2h-1.1zM114.5 79.3h3.8v5.6h-3.8zM114.8 72.2h1.7v1.7h-1.7zM114.8 75.4h1.7v1.7h-1.7zM116 66.9h.5v2.8h-.5zM117 66.9h.6v2.8h-.6zM118 75.3h1.7v1.9h-1.7zM118 72.1h1.7v1.9h-1.7z"/>
<path d="M118.1 66.9h.5v2.8h-.5zM119.1 66.9h.6v2.8h-.6zM119.3 79.3h3.8v5.6h-3.8zM120.2 66.9h.5v2.8h-.5zM121.2 75.3h1.7v1.9h-1.7zM121.2 72.1h1.7v1.9h-1.7zM121.2 66.9h.6v2.8h-.6zM122.3 66.9h.5v2.8h-.5zM123.3 66.9h.6v2.8h-.6zM123.8 73h1.2v1.2h-1.2zM123.8 75.1h1.2v1.2h-1.2zM124.4 66.9h.5v2.8h-.5z"/>
<path d="M125.4 66.9h.6v2.8h-.6zM126.4 66.9h.6v2.8h-.6zM127.5 66.9h.6v2.8h-.6zM128.9 75.4h1.7v1.7h-1.7zM128.9 72.2h1.7v1.7h-1.7zM129.7 61.5h2.8v.6h-2.8zM129.7 62.6h2.8v.6h-2.8zM129.7 64.7h2.8v.6h-2.8zM129.7 60.5h2.8v.5h-2.8zM129.7 63.6h2.8v.6h-2.8zM131.6 72.2h1.7v1.7h-1.7zM131.6 75.4h1.7v1.7h-1.7z"/>
<path d="M134.2 72.2h1.7v1.7h-1.7zM134.2 75.4h1.7v1.7h-1.7zM136.9 72.2h1.7v1.7h-1.7zM136.9 75.4h1.7v1.7h-1.7zM138.2 64.6h5.2v4.2h-5.2zM158.5 79.7h5.1v2.2h-5.1zM162.7 70.8h4.2v5.3h-4.2zM169.4 70.8h2.6v5.3h-2.6zM57.3 98.9h5v2.1h-5zM74.3 82.3h1.1v1.2h-1.1zM74.3 84.5h1.1v1.1h-1.1zM75.9 97.2h1.7v1.7h-1.7z"/>
<path d="M75.9 92.5h1.7v1.7h-1.7zM77.3 85.8h3.8v1.2h-3.8zM77.3 83.1h3.8v1.2h-3.8zM77.3 80.5h3.8v1.1h-3.8zM80.1 97.2h1.8v1.7h-1.8zM80.1 92.5h1.8v1.7h-1.8zM82.3 88.7h1.6v1.7h-1.6zM84.4 97.2h1.7v1.7h-1.7zM84.4 92.5h1.7v1.7h-1.7zM85.5 88.7h1.6v1.7h-1.6zM88.3 80.5h3.8v1.1h-3.8zM88.3 83.1h3.8v1.2h-3.8z"/>
<path d="M88.3 85.8h3.8v1.2h-3.8zM93.7 80.5h1.2v1.1h-1.2zM93.7 82.6h1.2v1.2h-1.2zM109.7 93.2h4.6M109.7 93.1h4.6M109.7 93h4.6M109.7 92.9h4.6M109.7 92.8h4.6M109.7 92.7h4.6M109.7 92.6h4.6M109.7 92.5h4.6M109.7 92.4h4.6"/>
<path d="M113.2 93.3v3.7h1.1v-4.8l-4.6 .1v1h4.6M113.2 96.9h1.1M113.2 96.8h1.1M113.2 96.7h1.1M113.2 96.6h1.1M113.2 96.5h1.1M113.2 96.4h1.1M113.2 96.3h1.1M113.2 96.2h1.1M113.2 96.1h1.1M113.2 96h1.1M113.2 95.9h1.1"/>
<path d="M113.2 95.8h1.1M113.2 95.7h1.1M113.2 95.6h1.1M113.2 95.5h1.1M113.2 95.4h1.1M113.2 95.3h1.1M113.2 95.2h1.1M113.2 95.1h1.1M113.2 95h1.1M113.2 94.9h1.1M113.2 94.8h1.1M113.2 94.7h1.1"/>
<path d="M113.2 94.6h1.1M113.2 94.5h1.1M113.2 94.4h1.1M113.2 94.3h1.1M113.2 94.2h1.1M113.2 94.1h1.1M113.2 94h1.1M113.2 93.9h1.1M113.2 93.8h1.1M113.2 93.7h1.1M113.2 93.6h1.1M113.2 93.5h1.1"/>
<path d="M113.2 93.4h1.1M128.8 99.4h1.9v1.7h-1.9zM132 99.4h1.9v1.7h-1.9zM132.4 88.6h1.7v1.9h-1.7zM132.4 85.4h1.7v1.9h-1.7zM135.6 87.4h3.2v2.7h-3.2zM135.6 81.6h3.2v2.6h-3.2zM136.1 94.8l.2-.1h1.2l.2 .3-.3 .3h-1.1l-.2-.2zM136.1 95.9l.2-.2h1.2l.2 .4-.3 .2h-1.1l-.2-.1zM136.1 96.9l.2-.1h1.2l.2 .3-.3 .3h-1.1l-.2-.2zM136.1 98l.2-.2h1.2l.2 .3-.3 .3h-1.1l-.2-.1zM136.1 99l.2-.1h1.2l.2 .3-.3 .3h-1.1l-.2-.2z"/>
<path d="M138.2 92.7h.3l.2 .3-.1 1.2-.3 .2-.2-.3v-1.2zM138.8 95.4h8.6v8.6h-8.6zM139.3 92.7h.3l.1 .3v1.2l-.3 .2-.3-.3v-1.2zM140.3 92.7h.3l.2 .3-.1 1.2-.3 .2-.2-.3v-1.2zM140.6 86.1h1.2v1.1h-1.2zM140.6 88.2h1.2v1.1h-1.2zM141.4 92.7h.2l.2 .3v1.2l-.3 .2-.3-.3v-1.2zM142.4 92.7h.3l.2 .3-.1 1.2-.3 .2-.2-.3v-1.2zM143 85.4h1.7v1.9h-1.7zM143 88.6h1.7v1.9h-1.7zM143.3 80.7h1.1v1.2h-1.1zM143.3 82.9h1.1v1.1h-1.1z"/>
<path d="M143.4 92.7h.3l.2 .3-.1 1.2-.2 .2-.3-.3v-1.2zM144.5 92.7h.3l.1 .3v1.2l-.3 .2-.2-.3v-1.2zM145.6 92.7h.3l.1 .3v1.2l-.3 .2-.3-.3v-1.2zM145.9 85.4h1.8v1.9h-1.8zM145.9 88.6h1.8v1.9h-1.8zM146.2 80.7h1.2v1.2h-1.2zM146.2 82.9h1.2v1.1h-1.2zM146.6 92.7h.3l.1 .3v1.2l-.3 .2-.2-.3v-1.2zM147.7 92.7h.3l.1 .3v1.2l-.3 .2-.3-.3v-1.2zM148.4 99l.3-.1h1.1l.3 .3-.3 .3h-1.1l-.3-.2zM148.4 96.9l.3-.1h1.1l.3 .3-.3 .3h-1.1l-.3-.2zM148.4 94.8l.3-.1h1.1l.3 .3-.3 .3h-1.1l-.3-.2z"/>
<path d="M148.4 98l.3-.2h1.1l.3 .3-.3 .3h-1.1l-.3-.1zM148.4 95.9l.3-.2h1.1l.3 .4-.3 .2h-1.1l-.3-.1zM148.9 86.1h1.2v1.1h-1.2zM148.9 88.2h1.2v1.1h-1.2zM151.2 81h1.9v1.7h-1.9zM151.4 92.7h1.9v1.7h-1.9zM151.5 88.4h1.7v1.9h-1.7zM151.5 85.2h1.7v1.9h-1.7zM152.3 96.5h1.2v1.1h-1.2zM152.3 99.7h1.2v1.1h-1.2zM154.4 81h1.9v1.7h-1.9zM154.5 96.5h1.1v1.1h-1.1z"/>
<path d="M154.5 99.7h1.1v1.1h-1.1zM154.5 88.2h1.7v1.7h-1.7zM154.5 85h1.7v1.7h-1.7zM154.6 92.7h1.9v1.7h-1.9zM158.5 90.4h5.1v2.1h-5.1zM165.7 95.7h5.1v2.1h-5.1zM165.7 85h5.1v2.2h-5.1zM57.3 109.6h5v2.1h-5zM64.5 114.9h5v2.1h-5zM64.5 104.2h5v2.2h-5zM114.3 114.9h2.1v3.8h-2.1zM117 105h2.6v3.2h-2.6z"/>
<path d="M119.1 114.9h2.1v3.8h-2.1zM122.8 105h2.7v3.2h-2.7zM123.9 114.9h2.1v3.8h-2.1zM128.8 102.3h1.9v1.7h-1.9zM132 102.3h1.9v1.7h-1.9zM132.1 112.2h1.7v1.7h-1.7zM132.1 109h1.7v1.7h-1.7zM135 112.2h1.7v1.7h-1.7zM135 109h1.7v1.7h-1.7zM136.1 103.2l.2-.1h1.2l.2 .3-.3 .3h-1.1l-.2-.2zM136.1 104.3l.2-.2h1.2l.2 .4-.3 .2h-1.1l-.2-.1zM136.1 100.1l.2-.2h1.2l.2 .3-.3 .3h-1.1l-.2-.1z"/>
<path d="M136.1 101.1l.2-.1h1.2l.2 .3-.3 .3h-1.1l-.2-.2zM136.1 102.2l.2-.2h1.2l.2 .3-.3 .3h-1.1l-.2-.1zM137.9 112.2h1.8v1.7h-1.8zM137.9 109h1.8v1.7h-1.8zM138.2 105.1h.3l.2 .2-.1 1.3-.3 .1-.2-.3v-1.1zM139.3 105.1h.3l.1 .2v1.3l-.3 .1-.3-.3v-1.1zM140.3 105.1h.3l.2 .2-.1 1.3-.3 .1-.2-.3v-1.1zM141.4 105.1h.2l.2 .2v1.3l-.3 .1-.3-.3v-1.1zM141.7 111.1h1.2v1.2h-1.2zM141.7 109h1.2v1.1h-1.2zM142.4 105.1h.3l.2 .2-.1 1.3-.3 .1-.2-.3v-1.1zM143.4 105.1h.3l.2 .2-.1 1.3-.2 .1-.3-.3v-1.1z"/>
<path d="M144.1 111.8h1.7v1.9h-1.7zM144.1 108.6h1.7v1.9h-1.7zM144.5 105.1h.3l.1 .2v1.3l-.3 .1-.2-.3v-1.1zM145.5 120h2.6v3.1h-2.6zM145.6 105.1h.3l.1 .2v1.3l-.3 .1-.3-.3v-1.1zM146.6 105.1h.3l.1 .2v1.3l-.3 .1-.2-.3v-1.1zM147.7 105.1h.3l.1 .2v1.3l-.3 .1-.3-.3v-1.1zM148.4 100.1l.3-.2h1.1l.3 .3-.3 .3h-1.1l-.3-.1zM148.4 104.3l.3-.2h1.1l.3 .4-.3 .2h-1.1l-.3-.1zM148.4 103.2l.3-.1h1.1l.3 .3-.3 .3h-1.1l-.3-.2zM148.4 101.1l.3-.1h1.1l.3 .3-.3 .3h-1.1l-.3-.2zM148.4 102.2l.3-.2h1.1l.3 .3-.3 .3h-1.1l-.3-.1z"/>
<path d="M150.4 113.5h1.9v1.7h-1.9zM150.5 110.6h1.7v1.7h-1.7zM151.3 120h2.7v3.1h-2.7zM153.6 113.5h1.9v1.7h-1.9zM153.7 110.6h1.7v1.7h-1.7zM158.5 111.7h5.1v2.1h-5.1zM158.5 101h5.1v2.2h-5.1zM165.7 117h5.1v2.1h-5.1zM165.7 106.4h5.1v2.1h-5.1zM57.3 130.9h5v2.1h-5zM57.3 120.2h5v2.1h-5zM64.5 136.2h5v2.1h-5z"/>
<path d="M64.5 125.5h5v2.2h-5zM72.2 134.2h5.9v3.2h-5.9zM79.7 138.1h3.8v2.1h-3.8zM79.7 133.2h3.8v2.2h-3.8zM84.2 127.7h2.6v3.2h-2.6zM90 127.7h2.7v3.2h-2.7zM92.9 135.7h3.8v6.9h-3.8zM98.8 139.8h1.7v1.9h-1.7zM99 127.8h1.8v1.9h-1.8zM99 124.6h1.8v1.9h-1.8zM99.1 135.7h1.3v2.3h-1.3zM99.1 130.6h1.3v2.4h-1.3z"/>
<path d="M101.1 130.6h1.3v2.4h-1.3zM102.2 139.9h1.8v1.7h-1.8zM103.1 128.2h1.1v1.1h-1.1zM103.1 126h1.1v1.2h-1.1zM103.1 135.7h1.3v2.3h-1.3zM103.1 130.6h1.3v2.4h-1.3zM105.3 139.9h1.9v1.7h-1.9zM116.7 128.1h6.9v3.8h-6.9zM130 130.6h3.2v2.7h-3.2zM130 124.8h3.2v2.6h-3.2zM139.6 135.2h3.8v2.1h-3.8zM139.6 130.3h3.8v2.2h-3.8z"/>
<path d="M139.6 125.5h3.8v2.2h-3.8zM140.4 139.6h1.1v1.2h-1.1zM142.5 139.6h1.2v1.2h-1.2zM152.8 128h3.8v6.9h-3.8zM158.5 136.2h5.1v2.1h-5.1zM158.5 122.3h5.1v2.2h-5.1zM165.7 127.7h5.1v2.1h-5.1zM57.3 157.5h5v2.2h-5zM57.3 146.9h5v2.1h-5zM64.5 152.2h5v2.1h-5zM72.2 141.4h5.9v3.2h-5.9zM79.7 142.9h3.8v2.1h-3.8z"/>
<path d="M79.9 157.7h1.1v1.2h-1.1zM82 157.7h1.2v1.2h-1.2zM83.1 150h35.7v25.2h-35.7zM91.3 149.5h1.2v1.1h-1.2zM91.3 147.3h1.2v1.2h-1.2zM93.7 149.5h1.2v1.1h-1.2zM93.7 147.3h1.2v1.2h-1.2zM97.5 149.5h1.1v1.1h-1.1zM97.5 147.3h1.1v1.2h-1.1zM98.8 143h1.7v1.9h-1.7zM102.8 143.6h1.1v1.2h-1.1zM104.6 149.5h1.2v1.1h-1.2z"/>
<path d="M104.6 147.3h1.2v1.2h-1.2zM104.9 143.6h1.2v1.2h-1.2zM107.8 149.5h1.2v1.1h-1.2zM107.8 147.3h1.2v1.2h-1.2zM111.6 149.5h1.1v1.1h-1.1zM111.6 147.3h1.1v1.2h-1.1zM118.5 157.2h1.2v1.2h-1.2zM118.5 159.9h1.2v1.1h-1.2zM120.6 159.9h1.2v1.1h-1.2zM120.6 157.2h1.2v1.2h-1.2zM158.5 157.5h5.1v2.2h-5.1zM158.5 146.9h5.1v2.1h-5.1z"/>
<path d="M165.7 152.2h5.1v2.1h-5.1zM165.7 141.5h5.1v2.2h-5.1zM57.3 168.2h5v2.1h-5zM64.5 173.5h5v2.1h-5zM64.5 162.8h5v2.2h-5zM68.4 177.1h1.7v1.9h-1.7zM72.1 179.6h2.5v3.2h-2.5zM72.2 174.6h2.6v3.2h-2.6zM74.3 168.3h1.7v1.9h-1.7zM74.3 165.1h1.7v1.9h-1.7zM75.1 171.6h1.1v1.2h-1.1zM77.2 171.6h1.2v1.2h-1.2z"/>
<path d="M78 168.3h1.7v1.9h-1.7zM78 165.1h1.7v1.9h-1.7zM78.1 174.6h2.6v3.2h-2.6zM78.3 179.6h2.5v3.2h-2.5zM79.9 160.1h1.1v1.2h-1.1zM82 160.1h1.2v1.2h-1.2zM86.6 171.6h4.5M86.6 171.5h4.5M86.6 171.4h4.5M86.6 171.3h4.5M86.6 171.2h4.5M86.6 171.1h4.5v.6h-4.5v-4.6h.5v4"/>
<path d="M86.6 171h.5M86.6 170.9h.5M86.6 170.8h.5M86.6 170.7h.5M86.6 170.6h.5M86.6 170.5h.5M86.6 170.4h.5M86.6 170.3h.5M86.6 170.2h.5M86.6 170.1h.5M86.6 170h.5M86.6 169.9h.5"/>
<path d="M86.6 169.8h.5M86.6 169.7h.5M86.6 169.6h.5M86.6 169.5h.5M86.6 169.4h.5M86.6 169.3h.5M86.6 169.2h.5M86.6 169.1h.5M86.6 169h.5M86.6 168.9h.5M86.6 168.8h.5M86.6 168.7h.5"/>
<path d="M86.6 168.6h.5M86.6 168.5h.5M86.6 168.4h.5M86.6 168.3h.5M86.6 168.2h.5M86.6 168.1h.5M86.6 168h.5M86.6 167.9h.5M86.6 167.8h.5M86.6 167.7h.5M86.6 167.6h.5M86.6 167.5h.5"/>
<path d="M86.6 167.4h.5M86.6 167.3h.5M86.6 167.2h.5M87.1 176.9h1.1v1.2h-1.1zM87.1 174.8h1.1v1.2h-1.1zM94.3 176.9h1.1v1.2h-1.1zM94.3 174.8h1.1v1.2h-1.1zM106 174.8h1.1v1.2h-1.1zM108.1 174.8h1.2v1.2h-1.2zM118.5 165.5h1.2v1.1h-1.2zM120.6 165.5h1.2v1.1h-1.2zM126.2 170.5h1.2v1.2h-1.2z"/>
<path d="M126.2 168.1h1.2v1.2h-1.2zM126.3 179.9h3.2v2.7h-3.2zM126.3 174.1h3.2v2.6h-3.2zM128.4 170.5h1.1v1.2h-1.1zM128.4 168.1h1.1v1.2h-1.1zM136.1 178.8h1.9v1.2h-1.9zM136.1 176.2h1.9v1.1h-1.9zM136.1 173.5h1.9v1.2h-1.9zM139.1 173.1h12.2v10h-12.2zM152.4 173.5h1.9v1.2h-1.9zM152.4 176.2h1.9v1.1h-1.9zM152.4 178.8h1.9v1.2h-1.9z"/>
<path d="M158.5 168.2h5.1v2.1h-5.1zM165.7 173.5h5.1v2.1h-5.1zM165.7 162.8h5.1v2.2h-5.1zM57.3 193.7h1.9v-.6h4.2v.6h1.9v.9h-1.9v.5h1.9v.8h-1.9v.6h-4.2v-.6h-1.9v-.8h1.9v-.5h-1.9zM57.7 187.3h1.8v1.7h-1.8zM57.7 184.1h1.8v1.7h-1.8zM58.8 190.9h.8v1.7h-.8zM58.8 197.1h.8v1.7h-.8zM60.2 197.1h.8v1.7h-.8zM60.2 190.9h.8v1.7h-.8zM61.5 197.1h.9v1.7h-.9zM61.5 190.9h.9v1.7h-.9z"/>
<path d="M62 184.1h1.7v1.7h-1.7zM62 187.3h1.7v1.7h-1.7zM62.9 197.1h.9v1.7h-.9zM62.9 190.9h.9v1.7h-.9zM67.1 197h5.4v2.4h-5.4zM67.1 190.8h5.4v2.4h-5.4zM68.4 180.3h1.7v1.9h-1.7zM72.3 184.4h1.9v1.7h-1.9zM73.2 187.6h1.2v1.1h-1.2zM75.3 187.6h1.2v1.1h-1.2zM75.5 184.4h1.9v1.7h-1.9zM76.4 192.7h1.7v1.6h-1.7z"/>
<path d="M76.4 195.9h1.7v1.6h-1.7zM76.5 199.8h3.2v2.5h-3.2zM130 199.5h1.7v1.9h-1.7zM131.6 181.4h1.1v1.2h-1.1zM133.7 181.4h1.2v1.2h-1.2zM136.1 181.5h1.9v1.2h-1.9zM136.6 195h1.7v1.7h-1.7zM136.6 192.1h1.7v1.7h-1.7zM136.6 198.2h1.7v1.7h-1.7zM139.8 195h1.7v1.7h-1.7zM139.8 192.1h1.7v1.7h-1.7zM139.8 198.2h1.7v1.7h-1.7z"/>
<path d="M143.6 198.2h3.4v1.8h-3.4zM143.6 195.9h3.4v1.8h-3.4zM143.6 193.6h3.4v1.7h-3.4zM143.6 191.2h3.4v1.8h-3.4zM145.5 188.2h6.5v2.5h-6.5zM152.4 181.5h1.9v1.2h-1.9zM156.1 181.4h1.1v1.2h-1.1zM158.2 181.4h1.2v1.2h-1.2zM162.5 184.1h1.6v1.7h-1.6zM164.7 188.2h4v4h-4zM165.7 184.1h1.6v1.7h-1.6zM169.7 188.1h6.4v3.2h-6.4z"/>
<path d="M176.9 192.4a54.9 54.9 0 0 0 0 24.3M53.8 209.7h2.4v3.2h-2.4zM54.7 201.7h1.9v1.7h-1.9zM57.9 201.7h1.9v1.7h-1.9zM59.1 218.8h2.7v3.2h-2.7zM59.9 209.7h2.5v3.2h-2.5zM61.2 204.9h1.7v1.7h-1.7zM61.2 201.7h1.7v1.7h-1.7zM64.4 204.9h1.7v1.7h-1.7zM64.4 201.7h1.7v1.7h-1.7zM65 218.8h2.6v3.2h-2.6zM65.3 209h4.8v4.7h-4.8z"/>
<path d="M67.6 204.9h1.7v1.7h-1.7zM67.6 201.7h1.7v1.7h-1.7zM71.3 210.5h2.4v1.7h-2.4zM76.5 206h3.2v2.4h-3.2zM76.5 210.2h3.2v2.5h-3.2zM76.5 216.4h3.2v2.4h-3.2zM82.6 204.7h35.7v35.7h-35.7zM83.9 200.9h1.1v1.2h-1.1zM83.9 203h1.1v1.2h-1.1zM89.5 200.9h1.1v1.2h-1.1zM89.5 203h1.1v1.2h-1.1zM95.1 200.9h1.1v1.2h-1.1z"/>
<path d="M95.1 203h1.1v1.2h-1.1zM99.8 200.9h1.2v1.2h-1.2zM99.8 203h1.2v1.2h-1.2zM104.9 200.9h1.2v1.2h-1.2zM104.9 203h1.2v1.2h-1.2zM110.5 200.9h1.2v1.2h-1.2zM110.5 203h1.2v1.2h-1.2zM112.6 200.9h1.2v1.2h-1.2zM112.6 203h1.2v1.2h-1.2zM115.8 200.9h1.2v1.2h-1.2zM115.8 203h1.2v1.2h-1.2zM119.4 211.3h2.6v3.2h-2.6z"/>
<path d="M119.4 200.2h2.6v3.1h-2.6zM122 204.9h1.1v1.2h-1.1zM122 208.1h1.1v1.2h-1.1zM124.1 204.9h1.2v1.2h-1.2zM124.1 208.1h1.2v1.2h-1.2zM125.2 211.3h2.7v3.2h-2.7zM125.2 200.2h2.7v3.1h-2.7zM130 209.4h1.7v1.7h-1.7zM130 206.2h1.7v1.7h-1.7zM130 202.7h1.7v1.9h-1.7zM132.9 208.9h1.1v1.2h-1.1zM132.9 206.8h1.1v1.1h-1.1z"/>
<path d="M133.2 203h1.1v1.2h-1.1zM133.2 200.9h1.1v1.2h-1.1zM136.6 209.4h1.7v1.7h-1.7zM136.6 206.8h1.7v1.7h-1.7zM136.6 201.2h1.7v1.7h-1.7zM136.6 203.8h1.7v1.7h-1.7zM139.8 206.8h1.7v1.7h-1.7zM139.8 209.4h1.7v1.7h-1.7zM139.8 201.2h1.7v1.7h-1.7zM139.8 203.8h1.7v1.7h-1.7zM143.6 207.5h3.4v1.7h-3.4zM143.6 205.2h3.4v1.7h-3.4z"/>
<path d="M143.6 202.9h3.4v1.7h-3.4zM143.6 200.6h3.4v1.7h-3.4zM143.6 209.8h3.4v1.7h-3.4zM146.1 219.2h7.4v3.4h-7.4zM169.3 219.6h7.2v3h-7.2zM176.9 216.7v62.6v-62.6M53.7 223.6v20M60.5 239.7h1.7v.6h-1.7zM60.5 238.4h1.7v.7h-1.7zM60.5 237.2h1.7v.6h-1.7zM60.5 234.7h1.7v.6h-1.7zM60.5 232.1h1.7v.7h-1.7z"/>
<path d="M60.5 229.6h1.7v.7h-1.7zM60.5 228.4h1.7v.6h-1.7zM60.5 227.1h1.7v.7h-1.7zM60.5 235.9h1.7v.7h-1.7zM60.5 233.4h1.7v.7h-1.7zM60.5 230.9h1.7v.6h-1.7zM60.5 225.8h1.7v.7h-1.7zM60.9 224.3h2.4v.8h-2.4zM66.6 239.1h1.7v.6h-1.7zM66.6 236.5h1.7v.7h-1.7zM66.6 235.3h1.7v.6h-1.7zM66.6 234h1.7v.7h-1.7z"/>
<path d="M66.6 232.8h1.7v.6h-1.7zM66.6 231.5h1.7v.7h-1.7zM66.6 230.3h1.7v.6h-1.7zM66.6 229h1.7v.7h-1.7zM66.6 227.7h1.7v.7h-1.7zM66.6 226.5h1.7v.6h-1.7zM66.6 237.8h1.7v.7h-1.7zM73.5 224.3h1.1v1.2h-1.1zM73.5 226.5h1.1v1.1h-1.1zM76.7 220.7h3.2v2.6h-3.2zM76.7 226.5h3.2v2.7h-3.2zM78.3 236.9h3.2v2.4h-3.2z"/>
<path d="M110.8 236.9h4M110.8 236.8h4M110.8 236.7h4M110.8 236.6h4M110.8 236.5h4M110.8 236.4h4M110.8 236.3h4M110.8 236.2h4M110.8 236.1h3.2v-2.9h.8v3.7h-4zM114 236.1h.8M114 236h.8M114 235.9h.8"/>
<path d="M114 235.8h.8M114 235.7h.8M114 235.6h.8M114 235.5h.8M114 235.4h.8M114 235.3h.8M114 235.2h.8M114 235.1h.8M114 235h.8M114 234.9h.8M114 234.8h.8M114 234.7h.8"/>
<path d="M114 234.6h.8M114 234.5h.8M114 234.4h.8M114 234.3h.8M114 234.2h.8M114 234.1h.8M114 234h.8M114 233.9h.8M114 233.8h.8M114 233.7h.8M114 233.6h.8M114 233.5h.8"/>
<path d="M114 233.4h.8M114 233.3h.8M119 238.7h1.2v1.2h-1.2zM119 231h1.2v1.2h-1.2zM119 233.4h1.2v1.2h-1.2zM119 236.1h1.2v1.1h-1.2zM119 225.7h1.2v1.1h-1.2zM119 228.3h1.2v1.2h-1.2zM119 223h1.2v1.2h-1.2zM121.2 228.3h1.1v1.2h-1.1zM121.2 238.7h1.1v1.2h-1.1zM121.2 231h1.1v1.2h-1.1z"/>
<path d="M121.2 233.4h1.1v1.2h-1.1zM121.2 236.1h1.1v1.1h-1.1zM121.2 225.7h1.1v1.1h-1.1zM121.2 223h1.1v1.2h-1.1zM125.3 223.3h1.9v1.7h-1.9zM125.3 220.1h1.9v1.7h-1.9zM125.5 236.3h1.6v1.7h-1.6zM125.5 233.1h1.6v1.7h-1.6zM125.5 226.2h1.6v1.7h-1.6zM128.5 223.3h1.9v1.7h-1.9zM128.5 220.1h1.9v1.7h-1.9zM128.7 236.3h1.6v1.7h-1.6z"/>
<path d="M128.7 233.1h1.6v1.7h-1.6zM128.7 226.2h1.6v1.7h-1.6zM132.1 229.8h1.7v1.9h-1.7zM132.1 233h1.7v1.9h-1.7zM132.1 239.4h1.7v1.9h-1.7zM132.1 236.2h1.7v1.9h-1.7zM135.7 225.2h5.7v3.8h-5.7zM135.7 220.4h5.7v3.8h-5.7zM136.3 231.5h3.4v2.8h-3.4zM136.3 236.4h3.4v2.7h-3.4zM148.7 235.6h4.8v2.1h-4.8zM148.7 230.3h4.8v2.1h-4.8z"/>
<path d="M168.4 235.6h4.8v2.1h-4.8zM168.4 230.3h4.8v2.1h-4.8zM53.7 243.6l-.1 .2-.4 .3-1.9 .1-.3 .5M60.5 241h1.7v.6h-1.7zM60.9 242.3h2.4v.9h-2.4zM66.6 240.3h1.7v.7h-1.7zM70.5 241.7h1.2v1.1h-1.2zM72.7 241.7h1.1v1.1h-1.1zM75.9 258.5h2.7v7.7h-2.7zM78.3 243.1h3.2v2.4h-3.2zM81.3 258.5h2.6v7.7h-2.6zM86.6 258.5h2.6v7.7h-2.6z"/>
<path d="M87.1 244.3h1.7v1.7h-1.7zM87.1 241.2h1.7v1.6h-1.7zM91.9 258.5h2.7v7.7h-2.7zM97.2 258.5h2.7v7.7h-2.7zM100.4 241.2h1.7v1.6h-1.7zM100.4 244.3h1.7v1.7h-1.7zM102.6 258.5h2.6v7.7h-2.6zM105.2 241.2h1.7v1.6h-1.7zM105.2 244.3h1.7v1.7h-1.7zM107.9 258.5h2.7v7.7h-2.7zM110.8 251.3h1.7v1.6h-1.7zM110.8 248.1h1.7v1.6h-1.7z"/>
<path d="M110.8 244.3h1.7v1.7h-1.7zM110.8 241.2h1.7v1.6h-1.7zM113.2 258.5h2.7v7.7h-2.7zM114 244.3h1.7v1.7h-1.7zM114 241.2h1.7v1.6h-1.7zM114 250.7h1.1v1.2h-1.1zM114 248.6h1.1v1.2h-1.1zM118 255h1.7v1.7h-1.7zM118 251.8h1.7v1.7h-1.7zM118.8 247.6h3.2v2.6h-3.2zM118.8 241.7h3.2v2.7h-3.2zM124.1 253.3h2.4v1.3h-2.4z"/>
<path d="M126.5 259.5h1.7v1.7h-1.7zM128.7 251.3h2.4v1.3h-2.4zM128.7 255.3h2.4v1.3h-2.4zM129.7 259.5h1.7v1.7h-1.7zM132.4 255h1.7v1.7h-1.7zM132.4 251.8h1.7v1.7h-1.7zM132.6 259.5h1.7v1.7h-1.7zM135.6 255h1.7v1.7h-1.7zM135.6 251.8h1.7v1.7h-1.7zM135.8 259.5h1.7v1.7h-1.7zM139.9 256.6h3.2v2.7h-3.2zM144.9 257.2h1.4v2.4h-1.4z"/>
<path d="M148.7 246.3h4.8v2.1h-4.8zM148.7 240.9h4.8v2.2h-4.8zM148.9 254.2h1.2v1.2h-1.2zM148.9 252.1h1.2v1.1h-1.2zM148.9 257.2h1.4v2.4h-1.4zM151.8 250.6h1.7v1.7h-1.7zM151.8 253.8h1.7v1.7h-1.7zM151.8 257.1h1.7v1.7h-1.7zM155 257.1h1.7v1.7h-1.7zM155 253.8h1.7v1.7h-1.7zM155 250.6h1.7v1.7h-1.7zM158.2 257.1h1.7v1.7h-1.7z"/>
<path d="M168.4 240.9h4.8v2.2h-4.8zM168.4 246.3h4.8v2.1h-4.8zM51 279.3v-34.6v34.6M75.9 268.9h2.7v7.7h-2.7zM81.3 268.9h2.6v7.7h-2.6zM86.6 268.9h2.6v7.7h-2.6zM91.9 268.9h2.7v7.7h-2.7zM97.2 268.9h2.7v7.7h-2.7zM102.6 268.9h2.6v7.7h-2.6zM107.9 268.9h2.7v7.7h-2.7zM113.2 268.9h2.7v7.7h-2.7zM123.8 265.4h1.7v1.7h-1.7z"/>
<path d="M123.8 262.2h1.7v1.7h-1.7zM127.3 279.3v-3.8v3.8M127.3 275.5l-.2-.2h-1.4l-.2 .2v3.8h-74.5M128.2 269.2h.9v2.8h-.9zM128.3 274.1h6.1v4.2h-6.1zM128.5 266h1.1M128.5 265.9h1.1M128.5 265.8h1.1M128.5 265.7l4.7 .1v-3.3h-4.4v3.3M128.5 265.7h.3M128.5 265.6h.3M128.5 265.5h.3"/>
<path d="M128.5 265.4h.3M128.5 265.3h.3M128.5 265.2h.3M128.5 265.1h.3M128.8 265h-.3v1.1h1.1v-.3M129.5 269.2h.9v2.8h-.9zM130.9 269.2h.9v2.8h-.9zM132.3 269.2h.8v2.8h-.8zM133.6 269.2h.9v2.8h-.9zM137.2 279.3v-3.8v3.8M137.2 275.5l-.2-.2h-1.3l-.3 .2v3.8h-8.1M137.2 279.3h39.7"/>
<path d="M139.9 262.5h3.2v2.7h-3.2zM144.9 262.2h1.4v2.4h-1.4zM145.5 272.9h7.2v2.6h-7.2zM146.9 262.2h1.4v2.4h-1.4zM148.9 262.2h1.4v2.4h-1.4zM151.6 267.6h7.2v2.6h-7.2zM151.8 260.3h1.7v1.7h-1.7zM154.9 263.5h1.9v1.7h-1.9zM155 260.3h1.7v1.7h-1.7zM158.1 263.5h1.9v1.7h-1.9zM158.2 260.3h1.7v1.7h-1.7z"/>
<circle cx="62.9" cy="31.5" r="1.05"/>
<circle cx="135.9" cy="31" r=".2"/>
<circle cx="135.9" cy="34.2" r=".2"/>
<circle cx="139.1" cy="31" r=".2"/>
<circle cx="139.1" cy="34.2" r=".2"/>
<circle cx="163.1" cy="30.7" r="1.05"/>
<circle cx="112.2" cy="43.7" r=".2"/>
<circle cx="112.2" cy="46.9" r=".2"/>
<circle cx="122.8" cy="43.5" r=".2"/>
<circle cx="122.8" cy="46.7" r=".2"/>
<circle cx="127.1" cy="73.1" r=".2"/>
<circle cx="127.1" cy="76.3" r=".2"/>
<circle cx="151.3" cy="108.5" r=".2"/>
<circle cx="154.5" cy="108.5" r=".2"/>
<circle cx="74.3" cy="157.8" r=".2"/>
<circle cx="74.3" cy="154.3" r=".2"/>
<circle cx="74.3" cy="150.9" r=".2"/>
<circle cx="77.5" cy="157.8" r=".2"/>
<circle cx="77.5" cy="150.9" r=".2"/>
<circle cx="77.5" cy="154.3" r=".2"/>
<circle cx="89.2" cy="159.2" r=".42"/>
<circle cx="89.2" cy="155.9" r=".42"/>
<circle cx="89.2" cy="157.6" r=".42"/>
<circle cx="90.9" cy="159.2" r=".42"/>
<circle cx="90.9" cy="155.9" r=".42"/>
<circle cx="90.9" cy="157.6" r=".42"/>
<circle cx="92.6" cy="155.9" r=".42"/>
<circle cx="92.6" cy="159.2" r=".42"/>
<circle cx="92.6" cy="157.6" r=".42"/>
<circle cx="94.2" cy="157.6" r=".42"/>
<circle cx="94.2" cy="155.9" r=".42"/>
<circle cx="94.2" cy="159.2" r=".42"/>
<circle cx="95.9" cy="155.9" r=".42"/>
<circle cx="95.9" cy="157.6" r=".42"/>
<circle cx="95.9" cy="159.2" r=".43"/>
<circle cx="97.6" cy="159.2" r=".42"/>
<circle cx="97.6" cy="155.9" r=".42"/>
<circle cx="97.6" cy="157.6" r=".42"/>
<circle cx="99.3" cy="159.2" r=".42"/>
<circle cx="99.3" cy="157.6" r=".42"/>
<circle cx="99.3" cy="155.9" r=".42"/>
<circle cx="101" cy="155.9" r=".42"/>
<circle cx="101" cy="157.6" r=".42"/>
<circle cx="101" cy="159.2" r=".43"/>
<circle cx="102.6" cy="159.2" r=".42"/>
<circle cx="102.6" cy="157.6" r=".42"/>
<circle cx="102.6" cy="155.9" r=".42"/>
<circle cx="104.3" cy="157.6" r=".42"/>
<circle cx="104.3" cy="155.9" r=".42"/>
<circle cx="104.3" cy="159.2" r=".42"/>
<circle cx="106" cy="157.6" r=".42"/>
<circle cx="106" cy="159.2" r=".42"/>
<circle cx="106" cy="155.9" r=".42"/>
<circle cx="107.7" cy="157.6" r=".42"/>
<circle cx="107.7" cy="155.9" r=".42"/>
<circle cx="107.7" cy="159.2" r=".42"/>
<circle cx="109.4" cy="159.2" r=".42"/>
<circle cx="109.4" cy="157.6" r=".42"/>
<circle cx="109.4" cy="155.9" r=".42"/>
<circle cx="111" cy="159.2" r=".42"/>
<circle cx="111" cy="157.6" r=".42"/>
<circle cx="111" cy="155.9" r=".42"/>
<circle cx="112.7" cy="157.6" r=".42"/>
<circle cx="112.7" cy="155.9" r=".42"/>
<circle cx="112.7" cy="159.2" r=".42"/>
<circle cx="140.4" cy="143.9" r=".2"/>
<circle cx="143.6" cy="143.9" r=".2"/>
<circle cx="71.9" cy="169.2" r=".2"/>
<circle cx="71.9" cy="166" r=".2"/>
<circle cx="74.3" cy="161" r=".2"/>
<circle cx="77.5" cy="161" r=".2"/>
<circle cx="89.2" cy="165.9" r=".42"/>
<circle cx="89.2" cy="169.3" r=".42"/>
<circle cx="89.2" cy="167.6" r=".42"/>
<circle cx="90.9" cy="165.9" r=".42"/>
<circle cx="90.9" cy="169.3" r=".42"/>
<circle cx="90.9" cy="167.6" r=".42"/>
<circle cx="92.6" cy="167.6" r=".42"/>
<circle cx="92.6" cy="165.9" r=".42"/>
<circle cx="92.6" cy="169.3" r=".42"/>
<circle cx="94.2" cy="169.3" r=".42"/>
<circle cx="94.2" cy="167.6" r=".42"/>
<circle cx="94.2" cy="165.9" r=".42"/>
<circle cx="95.9" cy="167.6" r=".42"/>
<circle cx="95.9" cy="169.3" r=".42"/>
<circle cx="95.9" cy="165.9" r=".43"/>
<circle cx="97.6" cy="167.6" r=".42"/>
<circle cx="97.6" cy="165.9" r=".42"/>
<circle cx="97.6" cy="169.3" r=".42"/>
<circle cx="99.3" cy="165.9" r=".42"/>
<circle cx="99.3" cy="167.6" r=".42"/>
<circle cx="99.3" cy="169.3" r=".42"/>
<circle cx="101" cy="169.3" r=".42"/>
<circle cx="101" cy="167.6" r=".42"/>
<circle cx="101" cy="165.9" r=".43"/>
<circle cx="102.6" cy="167.6" r=".42"/>
<circle cx="102.6" cy="169.3" r=".42"/>
<circle cx="102.6" cy="165.9" r=".42"/>
<circle cx="104.3" cy="169.3" r=".42"/>
<circle cx="104.3" cy="167.6" r=".43"/>
<circle cx="104.3" cy="165.9" r=".43"/>
<circle cx="106" cy="169.3" r=".42"/>
<circle cx="106" cy="167.6" r=".42"/>
<circle cx="106" cy="165.9" r=".42"/>
<circle cx="107.7" cy="167.6" r=".42"/>
<circle cx="107.7" cy="169.3" r=".42"/>
<circle cx="107.7" cy="165.9" r=".42"/>
<circle cx="109.4" cy="165.9" r=".42"/>
<circle cx="109.4" cy="169.3" r=".42"/>
<circle cx="109.4" cy="167.6" r=".42"/>
<circle cx="111" cy="165.9" r=".42"/>
<circle cx="111" cy="169.3" r=".42"/>
<circle cx="111" cy="167.6" r=".42"/>
<circle cx="112.7" cy="165.9" r=".42"/>
<circle cx="112.7" cy="169.3" r=".42"/>
<circle cx="112.7" cy="167.6" r=".42"/>
<circle cx="73.8" cy="218.5" r=".2"/>
<circle cx="88.7" cy="214.1" r=".42"/>
<circle cx="88.7" cy="217.5" r=".42"/>
<circle cx="88.7" cy="219.2" r=".42"/>
<circle cx="88.7" cy="215.8" r=".42"/>
<circle cx="88.7" cy="210.8" r=".42"/>
<circle cx="88.7" cy="212.5" r=".42"/>
<circle cx="90.4" cy="219.2" r=".42"/>
<circle cx="90.4" cy="217.5" r=".42"/>
<circle cx="90.4" cy="215.8" r=".42"/>
<circle cx="90.4" cy="214.1" r=".42"/>
<circle cx="90.4" cy="212.5" r=".42"/>
<circle cx="90.4" cy="210.8" r=".42"/>
<circle cx="92" cy="219.2" r=".42"/>
<circle cx="92" cy="217.5" r=".42"/>
<circle cx="92" cy="215.8" r=".42"/>
<circle cx="92" cy="214.1" r=".42"/>
<circle cx="92" cy="212.5" r=".42"/>
<circle cx="92" cy="210.8" r=".42"/>
<circle cx="93.7" cy="219.2" r=".42"/>
<circle cx="93.7" cy="217.5" r=".42"/>
<circle cx="93.7" cy="215.8" r=".42"/>
<circle cx="93.7" cy="214.1" r=".42"/>
<circle cx="93.7" cy="212.5" r=".42"/>
<circle cx="93.7" cy="210.8" r=".42"/>
<circle cx="95.4" cy="219.2" r=".42"/>
<circle cx="95.4" cy="217.5" r=".42"/>
<circle cx="95.4" cy="215.8" r=".42"/>
<circle cx="95.4" cy="214.1" r=".42"/>
<circle cx="95.4" cy="212.5" r=".42"/>
<circle cx="95.4" cy="210.8" r=".42"/>
<circle cx="97.1" cy="219.2" r=".42"/>
<circle cx="97.1" cy="217.5" r=".42"/>
<circle cx="97.1" cy="215.8" r=".42"/>
<circle cx="97.1" cy="214.1" r=".42"/>
<circle cx="97.1" cy="212.5" r=".42"/>
<circle cx="97.1" cy="210.8" r=".42"/>
<circle cx="98.7" cy="219.2" r=".42"/>
<circle cx="98.7" cy="217.5" r=".42"/>
<circle cx="98.7" cy="215.8" r=".42"/>
<circle cx="98.7" cy="214.1" r=".42"/>
<circle cx="98.7" cy="212.5" r=".42"/>
<circle cx="98.7" cy="210.8" r=".42"/>
<circle cx="100.4" cy="210.8" r=".42"/>
<circle cx="100.4" cy="219.2" r=".42"/>
<circle cx="100.4" cy="217.5" r=".42"/>
<circle cx="100.4" cy="215.8" r=".42"/>
<circle cx="100.4" cy="214.1" r=".42"/>
<circle cx="100.4" cy="212.5" r=".42"/>
<circle cx="102.1" cy="219.2" r=".42"/>
<circle cx="102.1" cy="217.5" r=".42"/>
<circle cx="102.1" cy="215.8" r=".42"/>
<circle cx="102.1" cy="214.1" r=".42"/>
<circle cx="102.1" cy="212.5" r=".42"/>
<circle cx="102.1" cy="210.8" r=".42"/>
<circle cx="103.8" cy="219.2" r=".42"/>
<circle cx="103.8" cy="217.5" r=".42"/>
<circle cx="103.8" cy="215.8" r=".42"/>
<circle cx="103.8" cy="214.1" r=".42"/>
<circle cx="103.8" cy="212.5" r=".42"/>
<circle cx="103.8" cy="210.8" r=".42"/>
<circle cx="105.5" cy="219.2" r=".42"/>
<circle cx="105.5" cy="217.5" r=".42"/>
<circle cx="105.5" cy="215.8" r=".42"/>
<circle cx="105.5" cy="214.1" r=".42"/>
<circle cx="105.5" cy="212.5" r=".42"/>
<circle cx="105.5" cy="210.8" r=".42"/>
<circle cx="107.2" cy="219.2" r=".42"/>
<circle cx="107.2" cy="217.5" r=".42"/>
<circle cx="107.2" cy="215.8" r=".42"/>
<circle cx="107.2" cy="214.1" r=".42"/>
<circle cx="107.2" cy="212.5" r=".42"/>
<circle cx="107.2" cy="210.8" r=".42"/>
<circle cx="108.8" cy="219.2" r=".42"/>
<circle cx="108.8" cy="217.5" r=".42"/>
<circle cx="108.8" cy="215.8" r=".42"/>
<circle cx="108.8" cy="214.1" r=".42"/>
<circle cx="108.8" cy="212.5" r=".42"/>
<circle cx="108.8" cy="210.8" r=".42"/>
<circle cx="110.5" cy="214.1" r=".42"/>
<circle cx="110.5" cy="217.5" r=".42"/>
<circle cx="110.5" cy="212.5" r=".42"/>
<circle cx="110.5" cy="215.8" r=".42"/>
<circle cx="110.5" cy="210.8" r=".42"/>
<circle cx="110.5" cy="219.2" r=".42"/>
<circle cx="112.2" cy="214.1" r=".42"/>
<circle cx="112.2" cy="215.8" r=".42"/>
<circle cx="112.2" cy="210.8" r=".42"/>
<circle cx="112.2" cy="219.2" r=".42"/>
<circle cx="112.2" cy="217.5" r=".42"/>
<circle cx="112.2" cy="212.5" r=".42"/>
<circle cx="73.8" cy="221.7" r=".2"/>
<circle cx="88.7" cy="229.2" r=".42"/>
<circle cx="88.7" cy="234.3" r=".42"/>
<circle cx="88.7" cy="232.6" r=".42"/>
<circle cx="88.7" cy="220.9" r=".42"/>
<circle cx="88.7" cy="222.5" r=".42"/>
<circle cx="88.7" cy="227.6" r=".42"/>
<circle cx="88.7" cy="224.2" r=".42"/>
<circle cx="88.7" cy="230.9" r=".42"/>
<circle cx="88.7" cy="225.9" r=".42"/>
<circle cx="90.4" cy="225.9" r=".42"/>
<circle cx="90.4" cy="224.2" r=".42"/>
<circle cx="90.4" cy="234.3" r=".42"/>
<circle cx="90.4" cy="222.5" r=".42"/>
<circle cx="90.4" cy="220.9" r=".42"/>
<circle cx="90.4" cy="232.6" r=".42"/>
<circle cx="90.4" cy="230.9" r=".42"/>
<circle cx="90.4" cy="229.2" r=".42"/>
<circle cx="90.4" cy="227.6" r=".42"/>
<circle cx="92" cy="224.2" r=".42"/>
<circle cx="92" cy="234.3" r=".42"/>
<circle cx="92" cy="222.5" r=".42"/>
<circle cx="92" cy="232.6" r=".42"/>
<circle cx="92" cy="220.9" r=".42"/>
<circle cx="92" cy="230.9" r=".42"/>
<circle cx="92" cy="229.2" r=".42"/>
<circle cx="92" cy="227.6" r=".42"/>
<circle cx="92" cy="225.9" r=".42"/>
<circle cx="93.7" cy="224.2" r=".42"/>
<circle cx="93.7" cy="234.3" r=".42"/>
<circle cx="93.7" cy="222.5" r=".42"/>
<circle cx="93.7" cy="220.9" r=".42"/>
<circle cx="93.7" cy="232.6" r=".42"/>
<circle cx="93.7" cy="230.9" r=".42"/>
<circle cx="93.7" cy="229.2" r=".42"/>
<circle cx="93.7" cy="227.6" r=".42"/>
<circle cx="93.7" cy="225.9" r=".42"/>
<circle cx="95.4" cy="234.3" r=".42"/>
<circle cx="95.4" cy="224.2" r=".42"/>
<circle cx="95.4" cy="222.5" r=".42"/>
<circle cx="95.4" cy="232.6" r=".42"/>
<circle cx="95.4" cy="220.9" r=".42"/>
<circle cx="95.4" cy="230.9" r=".42"/>
<circle cx="95.4" cy="229.2" r=".42"/>
<circle cx="95.4" cy="227.6" r=".42"/>
<circle cx="95.4" cy="225.9" r=".42"/>
<circle cx="97.1" cy="224.2" r=".42"/>
<circle cx="97.1" cy="234.3" r=".42"/>
<circle cx="97.1" cy="222.5" r=".42"/>
<circle cx="97.1" cy="232.6" r=".42"/>
<circle cx="97.1" cy="220.9" r=".42"/>
<circle cx="97.1" cy="230.9" r=".42"/>
<circle cx="97.1" cy="229.2" r=".42"/>
<circle cx="97.1" cy="227.6" r=".42"/>
<circle cx="97.1" cy="225.9" r=".42"/>
<circle cx="98.7" cy="234.3" r=".42"/>
<circle cx="98.7" cy="232.6" r=".42"/>
<circle cx="98.7" cy="230.9" r=".42"/>
<circle cx="98.7" cy="229.2" r=".42"/>
<circle cx="98.7" cy="227.6" r=".42"/>
<circle cx="98.7" cy="225.9" r=".42"/>
<circle cx="100.4" cy="234.3" r=".42"/>
<circle cx="100.4" cy="232.6" r=".42"/>
<circle cx="100.4" cy="230.9" r=".42"/>
<circle cx="100.4" cy="229.2" r=".42"/>
<circle cx="100.4" cy="227.6" r=".42"/>
<circle cx="100.4" cy="225.9" r=".42"/>
<circle cx="102.1" cy="234.3" r=".42"/>
<circle cx="102.1" cy="232.6" r=".42"/>
<circle cx="102.1" cy="230.9" r=".42"/>
<circle cx="102.1" cy="229.2" r=".42"/>
<circle cx="102.1" cy="227.6" r=".42"/>
<circle cx="102.1" cy="225.9" r=".42"/>
<circle cx="103.8" cy="234.3" r=".42"/>
<circle cx="103.8" cy="232.6" r=".42"/>
<circle cx="103.8" cy="230.9" r=".42"/>
<circle cx="103.8" cy="229.2" r=".42"/>
<circle cx="103.8" cy="227.6" r=".42"/>
<circle cx="103.8" cy="225.9" r=".42"/>
<circle cx="103.8" cy="224.2" r=".42"/>
<circle cx="103.8" cy="222.5" r=".42"/>
<circle cx="103.8" cy="220.9" r=".42"/>
<circle cx="105.5" cy="234.3" r=".42"/>
<circle cx="105.5" cy="232.6" r=".42"/>
<circle cx="105.5" cy="230.9" r=".42"/>
<circle cx="105.5" cy="229.2" r=".42"/>
<circle cx="105.5" cy="227.6" r=".42"/>
<circle cx="105.5" cy="225.9" r=".42"/>
<circle cx="105.5" cy="224.2" r=".42"/>
<circle cx="105.5" cy="222.5" r=".42"/>
<circle cx="105.5" cy="220.9" r=".42"/>
<circle cx="107.2" cy="234.3" r=".42"/>
<circle cx="107.2" cy="232.6" r=".42"/>
<circle cx="107.2" cy="230.9" r=".42"/>
<circle cx="107.2" cy="229.2" r=".42"/>
<circle cx="107.2" cy="227.6" r=".42"/>
<circle cx="107.2" cy="225.9" r=".42"/>
<circle cx="107.2" cy="224.2" r=".42"/>
<circle cx="107.2" cy="222.5" r=".42"/>
<circle cx="107.2" cy="220.9" r=".42"/>
<circle cx="108.8" cy="234.3" r=".42"/>
<circle cx="108.8" cy="232.6" r=".42"/>
<circle cx="108.8" cy="230.9" r=".42"/>
<circle cx="108.8" cy="229.2" r=".42"/>
<circle cx="108.8" cy="227.6" r=".42"/>
<circle cx="108.8" cy="225.9" r=".42"/>
<circle cx="108.8" cy="224.2" r=".42"/>
<circle cx="108.8" cy="222.5" r=".42"/>
<circle cx="108.8" cy="220.9" r=".42"/>
<circle cx="110.5" cy="232.6" r=".42"/>
<circle cx="110.5" cy="230.9" r=".42"/>
<circle cx="110.5" cy="227.6" r=".42"/>
<circle cx="110.5" cy="224.2" r=".42"/>
<circle cx="110.5" cy="222.5" r=".42"/>
<circle cx="110.5" cy="220.9" r=".42"/>
<circle cx="110.5" cy="229.2" r=".42"/>
<circle cx="110.5" cy="225.9" r=".42"/>
<circle cx="110.5" cy="234.3" r=".42"/>
<circle cx="112.2" cy="234.3" r=".42"/>
<circle cx="112.2" cy="232.6" r=".42"/>
<circle cx="112.2" cy="220.9" r=".42"/>
<circle cx="112.2" cy="224.2" r=".42"/>
<circle cx="112.2" cy="229.2" r=".42"/>
<circle cx="112.2" cy="225.9" r=".42"/>
<circle cx="112.2" cy="222.5" r=".42"/>
<circle cx="112.2" cy="230.9" r=".42"/>
<circle cx="112.2" cy="227.6" r=".42"/>
<circle cx="62.3" cy="259.8" r="1.05"/>
<circle cx="95.1" cy="251.6" r=".2"/>
<circle cx="95.1" cy="242" r=".2"/>
<circle cx="95.1" cy="248.4" r=".2"/>
<circle cx="95.1" cy="245.2" r=".2"/>
<circle cx="108.7" cy="242" r=".2"/>
<circle cx="108.7" cy="245.2" r=".2"/>
<circle cx="126.3" cy="240.4" r=".2"/>
<circle cx="129.5" cy="240.4" r=".2"/>
<circle cx="129.4" cy="263" r=".24"/>
<circle cx="129.4" cy="264.1" r=".25"/>
<circle cx="130.4" cy="263" r=".24"/>
<circle cx="130.4" cy="264.1" r=".25"/>
<circle cx="130.4" cy="265.2" r=".25"/>
<circle cx="131.5" cy="263" r=".24"/>
<circle cx="131.5" cy="265.1" r=".24"/>
<circle cx="131.5" cy="264.1" r=".25"/>
<circle cx="132.5" cy="263" r=".24"/>
<circle cx="132.5" cy="264.1" r=".24"/>
<circle cx="132.5" cy="265.1" r=".24"/>
</g>
<g fill="none" stroke="#000" stroke-width=".32">
<path d="M88.5 15.5v-.5h-10.7v.5M96.2 13.1h2.9v18.4h-2.9zM102.8 11.3v2.8M119.6 11.3v2.8M142.8 16v13.4h-13.3v-13.4h17v-2.9h-9.3v2.9M155.1 15.8h5.8v2.9h-5.8zM51.3 35.2h2.9v5.9h-2.9zM71.7 33.4h4.5v2.9h-4.5zM77.8 30.4v.6h10.7v-.6M99.3 31.9v2.3h-2.1v2.6h.2M102.8 20.5v5M104.9 30.9h1.6"/>
<path d="M105.9 37.3h1.3v5.2h3.8v-.7h12.3M107.5 32.2v2.3l.1 .2h1.4v-1.6h2.9v2.5h11.3v.6M108.2 36h-.6v5.4h.6v-1.1h-.6M110.8 34.4h1.1M110.8 36h.6v5.4h-.6v-1.1h.6M111.4 33.9v1.1M115.8 30.9h1.7M119.6 20.5v5M128.4 37.6v1.1M130 35h2.2v1.8M132.2 39.5v1.9h-2.2M150 20h-.5v5.4h5.8"/>
<path d="M154.3 20h5.8v5.4h-.5M155.1 35h13.3v13.3h-13.3zM166.8 30.7h7.7v3.5h-7.7zM54.3 40.1v7.3M57.3 56.4h-.7v1.6M58.7 53.8h-1.3v4.1M61.2 40.1v7.3M64.5 53.8h3.8v15.6h-3.5M66.7 53.8v15.5M108.2 40.6h-.3v.8M110.3 56.5h.5M110.8 40.6h.3v.8"/>
<path d="M117.2 47.8v.2M122.6 48v.3M133.2 57.6h.6M146.3 58.8h-2.9v4.9M152.4 58.8h13.3M171.6 58.8h1.1M51.4 69.9h4.5v2.9h-4.5zM56.6 65.2v1.6h.7M57.4 65.3v4.1h1.3M81.8 77.1h5.9v10.6h-1.9a1.06 1.06 0 0 0-1.1-1.1 1.06 1.06 0 0 0-1 1.1h-1.9zM110.6 61.9h.2M113.8 78.7h10.1v6.9h-10.1z"/>
<path d="M115.4 64.2v-11.7h13.3v13.4h-11.6l-1.7-1.7M120.4 70.4v.3M125.8 70.4v.5M133 71.2v-2.4h3.5v9.2h-24.7v-6.7h24.7M133.2 62.9h.3M135.2 69.9l-1.7 .6 .6-.5 .3 .5-1 .1M143.3 71.7h18.7v3h-18.7zM143.4 69.6v1.8h18.6M162.1 78.9v-1.3h5.1v6.6M167.9 71.4h.8M176 61.3h3.1v7.6h-3.1M176 60v11.4h-3.1"/>
<path d="M60.9 98.1v-1.3h5v6.6M71.7 87.7v6.4h-20.3M71.9 92h2.4v-4.3h-22.9v6.4v-.2M73.9 88l-1 .1 .4 .6 .6-.6-1.7 .7M75.4 97.6h-.3v.8M75.4 93h-.5v5.4h.5v-1.1h-.5M78.1 91.4h1M78.1 93h.5v5.4h-.5v-1.1h.5M78.1 97.6h.2v.8M78.6 90.9v1.1M79.7 97.6h-.3v.8M79.7 93h-.6v5.4h.6v-1.1h-.6"/>
<path d="M82.3 91.4h1.1M82.3 97.6h.3v.8M82.3 93h.6v5.4h-.6v-1.1h.6M82.9 90.9v1.1M83.9 97.6h-.2v.8M83.9 93h-.5v5.4h.5v-1.1h-.5M86.6 91.4h1.1M86.6 97.6h.2v.8M86.6 93h.5v5.4h-.5v-1.1h.5M87.1 90.9v1.1M97.5 93h16v11.2h-16zM134.8 88.5v2.4h.8"/>
<path d="M134.8 83.5v-2.7h4.8v2.7M137.2 91.7h-3.4v5.9h-3.2M139.6 88.5v2.4h-1.8M142.3 91.4h14.9v-7.4h-8.8v.5h-6.4v-4.5h-10.9v10.1l-2.2 2.1h-14.3v5.4h14.3M162.1 82.7v6.9M162.1 93.3v6.9M167.2 88v6.9M167.2 98.6v7M60.9 101.8v7M60.9 112.5v6.9M65.9 107.2v6.9M65.9 117.8v7"/>
<path d="M113.2 119.4h13.9v8h-13.9zM116.2 107.2v1.8h2.4M118.6 104.2h-2.4v.8M123.6 104.2h2.7v4.8h-2.7M147.3 119.2h-2.6v4.8h2.6M152.4 119.2h2.4v1.8M162.1 104v6.9M162.1 114.6v7M167.2 109.3v6.9M167.2 120v6.9M60.9 123.1v7M60.9 133.8v6.7h5v-1.4"/>
<path d="M65.9 128.5v6.9M84.2 132.2h8v13.9h-8zM86.1 126.9h-2.7v4.8h2.7M91.1 126.9h2.4v1.9M93.5 130.9v.8h-2.4M98.3 132.5v3.7M101.2 136.2h1.1M105.2 132.5v3.7M129.2 126.6v-2.6h4.8v2.6M129.2 131.7v2.4h.8M134 131.7v2.4h-1.8M144.1 124.5h8v13.8h-8z"/>
<path d="M154.8 123.1v.9h-2.4M162.1 125.3v6.7h5.1v-1.4M162.1 135.4v-1.3h5.1v6.6M162.1 139.1v7M60.9 146.1v-1.4h5v6.7M60.9 149.8v6.9M65.9 155.1v7M66.6 144.2h4.5v2.7h8.3v9h-7.2v-6.1h-3.2M73.8 145.3h-2.1v-11.8h6.9v11.8h-2.4M74.6 145.8h1.1M75.1 145.3v1M97.5 144.2h.8"/>
<path d="M138.6 151.1h10.1v-6.6h8l.2 .2v15.5l-.2 .3h-18.1zM155.8 143.4l.5 .3-.7 .4zM156.5 142.9l-.9 1.2M156.9 144.4h-3.2v-4l3.2 .1v4.2M162.1 149.8v6.9M167.2 144.5v6.9M167.2 155.1v7M58.9 178.1h8.2v-1.9h3.5v-2.7h11.2v10.1h-15.7v-.8h-7.2zM60.9 160.5v6.9M60.9 171.1v6.7h5v-1.4M65.9 165.8v6.9M71.4 176.7v1.9h2.4"/>
<path d="M73.8 173.8h-2.4v.8M75.1 179.1h-3.5v4.3h3.2M77.9 179.1h3.4v4.3h-3.4M78.9 173.8h2.6v4.8h-2.6M127.4 173.2h-1.9v2.4M129.5 173.2h.8v2.4M136.8 172.8v-1h16.8v1M162.1 171.1v6.7h5.1v-1.4M162.1 160.5v6.9M167.2 165.8v6.9M57.8 196.7v1.6h.3M58.1 191.4h-.3v1.5"/>
<path d="M64.4 191.4l.3 .4v1.1M64.7 196.7v1.6h-.2M66.6 190.2v9.7M73 190.2v9.7M121 199.4h-2.4v.8M126 199.4h2.7v4.8h-2.7M130.3 180.7v2.7h-4.8v-2.7M136.8 183.4v1h16.8v-1M138.8 190.6v-3.5h4v3.7M140 188l-.7 .4 .6 .4 .1-.8-.8 1.2M152.9 189.8h11M157.7 186.6h5.9v2.9h-5.9z"/>
<path d="M176.9 191.1v1.3M176.9 192.4a54.9 54.9 0 0 0 0 24.3M56.7 209.2h-3.5v4.3h3.5M59.7 206.3h.8M59.7 209.2h3.2v4.3h-3.4M61 218h-2.6v4.8h2.6M63.4 208.4h7.5v1.4h3.4v3.2h-3.4v1.3h-7.5zM63.9 208.7v5.3h.3v-5.3h-.5v5.6M64.5 208.4v5.9M66.1 218h2.4v1.9M75.9 202.8v-3.5h4.3v3.5M75.9 205.5v3.5h4.3v-3.2"/>
<path d="M75.9 213.2v-3.5h4.3v3.5M75.9 215.9v3.5h4.3v-3.2M77.8 219.9h-1.9v2.4M79.9 219.9h.8v2.4M86.8 208.9h27.3v27.3h-27.3zM112.2 200.2v-1.4h23.7v-8.2h6.9v21.6h-13.8v-2h-8.5v-5.2h-8.4v-.2M118.5 218.1l1.5 1.5M118.6 213.5v1.8h2.4M118.6 202.3v1.9h2.4M119.4 218.3l.6 1.3-1.3-.5zM121 210.5h-2.4v.8M126 210.5h2.7v4.8h-2.7"/>
<path d="M135.1 219.6h6.9v10.1h-6.9zM146.8 212.4v5.9M176.9 216.7v2.1M54.6 228.4h3v13.3h-3zM59.9 224.3v18.9M64.4 224h2.5v1.2h1.1v.3M68.5 222v.8h-2.4M75.9 227.4v2.6h4.8v-2.6M77.8 239.5v-3.2h4.3v3.5M122.8 221.7v-4h-4.8v22.7h5.9v-18.4h-5.6M135.6 230.8h4.8v9.1h-4.8zM136.9 235.1h2.2v.5h-2.2z"/>
<path d="M138 234.8v.3M138 235.6v.3M143.6 232.1v-5.3h4v20.3h-5.8v-15h5.8M144.3 229.1l1.7 1.7M144.3 229.1l1.3 .6-.8 .7zM152.4 233.2v1.6M152.4 238.5v1.7M154.3 221.7h13.8M159.9 225.2h15.1v2.9h-15.1zM169.5 229.5v-.8h-17.1v.8M169.5 233.2v1.6M169.5 238.5v1.7"/>
<path d="M68 242v.3h-1.1v1.1h-2.5M77.8 242.6v3.4h4.3v-3.4M107.9 240.1h-24.5v7h7.2v7.2h6.9v-1.9h12.3v-4.8l.5-.5h3.5M112.5 240.1h4.3v7h-1.2M118 248.4v2.7h4.8v-2.7M119.9 240.9h-1.9v2.4M122 240.9h.8v2.4M125.8 255.3v1.9h2.1M127.9 250.8h-2.1v1.8M129.5 253.4v1.1M133.5 250.5v.6M136.4 250.5v.6"/>
<path d="M139.1 258.5v-2.7h4.8v2.7M144.1 259.1v3.7M144.4 256.4h17.6v-2.4h12.5v9.8h-13v1.9h-14.4v1.3h-2.8v-3.5M147.1 259.1h1M151.1 259.1v3.7M152.4 249.2v.8h17.1v-.8M152.4 243.9v1.6M169.5 243.9v1.6M67.9 266h5.9v2.9h-5.9zM75.1 262.3h-.5v10.6h.5M116.7 262.3h.5v10.6h-.5M117.8 263.6h2.9v15.2h-2.9z"/>
<path d="M123.5 279.4v1.5h15.7v-1.5M124.7 270.6h-1.2v3.2M138 270.6h1.2v3.2M139.1 263.6v2.4h.8M143.9 263.6v2.4h-1.9M154.8 271v5.9h-5.3v-.5M154.8 266.8v-.6h-5.3v5.9M157.5 275h5.8v3h-5.8zM160.9 260.4h9.1v2.9h-9.1z"/>
<circle cx="120.4" cy="154.1" r="1.55"/>
<circle cx="132.9" cy="173.2" r="1.55"/>
<circle cx="132.9" cy="177.5" r="1.55"/>
<circle cx="158.5" cy="178.6" r="1.55"/>
<circle cx="107.6" cy="195.6" r="1.55"/>
<circle cx="111.9" cy="195.6" r="1.55"/>
<circle cx="135.1" cy="188.7" r="1.55"/>
</g>
<g fill="none" stroke="#000" stroke-width=".25">
<path d="M75.1 14.2h1.6l-.8 1.4zM75.4 14.2v.2h1l-.1 .2h-.8l.1 .2h.6l-.3 .5-.2-.3h.2M55.1 36h5.4M55.1 38.7h5.4M61.8 36.3v5.3M64.5 36.3v5.3M77.2 31.5h6v2.7h-6zM83.9 34.2h5.4M83.9 31.5h5.4M93 34.2h5.3M93 31.5h5.3M112.2 36v5.4"/>
<path d="M114.6 32.8h.3l-.2-.3-.3 .5h.5l.1 .1h-.7l-.1 .2h1v.2M114.7 32.2l.8 1.3h-1.6zM114.8 36v5.4M117.5 36v5.4M118.8 35.2h3.8M118.8 33.1h3.8M120.2 36v5.4M120.4 36v5.4M123.1 36v5.4M123.4 36v5.4M126 36v5.4M134.5 32.8h6v2.7h-6z"/>
<path d="M134.5 29.6h6v2.7h-6zM135.1 35.8h5.3M135.1 38.4h5.3M140.9 29.9v5.3M141.8 39.5v5.3M143.6 29.9v5.3M144.1 35.8h-2.2v2.6h2.2M144.4 32.6v1.6h2.1v-1.6M144.4 31.5v-1.6h2.1v1.6M144.4 39.5v5.3M145.2 39.5v5.3M145.8 35.8h2.2v2.6h-2.2"/>
<path d="M147.9 39.5v5.3M157.6 30.8h.2l-.2-.3-.3 .4h.6l.1 .2h-.8l-.1 .2h1.1v.2M157.6 30.2l.8 1.3h-1.6zM51.9 45.1h1.6M51.9 44.3h1.6l-.8 .8zM52.1 41.8l1.1 1.1M52.1 42.6l1.1 1.1M52.1 41.8l.8 .6-.3 .2zM52.1 42.6l.8 .6-.3 .2zM52.6 58.2l1.3 .8-1.3 .8zM52.7 43.8v.5M52.7 45.1v.6"/>
<path d="M53.4 58.9v.3l.3-.2-.5-.3v.5l-.2 .2v-.8l-.2-.2v1.1h-.2M53.8 53.3v1.6h2.1v-1.6M53.8 52.3v-1.6h2.1v1.6M61.8 42.7v5.3M64.5 42.7v5.3M107.9 50.7v5.3M107.9 57.1v5.3M108.2 42.7v5.3M110.6 50.7v5.3M110.6 57.1v5.3M110.8 42.3h2.7v6.1h-2.7zM115.4 45.9h-1.6v2.1h1.6"/>
<path d="M116.4 45.9h1.6v2.1h-1.6M121.5 42h2.7v6.1h-2.7zM125.5 42.4v5.4M130.8 44.3v-2.3h-2.6v6.1h2.6v-2.2M133.2 48h5.4M133.2 50.7h5.4M134 56.3h5.3M134 58.9h5.3M135.9 52.3h-1.6v2.1h1.6M136.9 52.3h1.7v2.1h-1.7M159.9 50.4h5.3M159.9 53.1h5.3"/>
<path d="M167.3 53.1h5.4M167.3 50.4h5.4M57 74.1v3.8M59.1 74.1v3.8M63.1 73.3v5.4M65.8 73.3v5.4M70.3 77.1h5.4M70.3 79.7h5.4M109.5 74.1v-1.6h2.1v1.6M109.5 75.2v1.6h2.1v-1.6M110.3 65.9v1.6h-2.1v-1.6M110.3 64.8v-1.6h-2.1v1.6"/>
<path d="M111.9 72.8v3.7M114 72.8v3.7M114.1 70.1l1.6-.3-.4 1.5zM114.3 72v5.3M115.2 70.1l.2 .2 .1-.3-.6 .1 .4 .4v.2l-.6-.6-.2 .1 .7 .7-.1 .2 .2 .2M117 72v5.3M120.2 73.9v-2.3h-2.7v2.3M120.2 75.5v2.2h-2.7v-2.2M120.7 73.9v-2.3h2.7v2.5M123.4 72.5h2.1v1.6M123.4 75.2v2.5h-2.7v-2.2M125.5 75.2v1.6h-2.1"/>
<path d="M125.8 71.6h2.6v6.1h-2.6zM131.1 72v5.3M133.8 72v5.3M136.4 72v5.3M139.1 72v5.3M58.1 96.9h1.6l-.8 1.3zM58.4 96.9v.2h1.1l-.1 .2h-.8l.1 .2h.5l-.3 .4-.2-.3h.3M73.8 83.5v-1.6h2.1v1.6M73.8 84.5v1.6h2.1v-1.6M82.1 90.9h5.3M82.1 88.2h5.3M92.6 86.4l1.3-.8v1.6z"/>
<path d="M93.3 80.3v3.7M93.9 85.9h-.2v1l-.2-.1v-.8l-.2 .1v.6l-.4-.3 .3-.2v.2M95.4 80.3v3.7M130.6 98.9h-2.3v2.7h2.3M131.9 87.2v-2.3h2.7v2.3M131.9 88.8v2.2h2.7v-2.2M132.2 98.9h2.2v2.7h-2.2M136.1 90.9h1.1M136.7 90.4v1M140.1 87.2v-1.6h2.2v1.6M140.1 88.2v1.7h2.2v-1.7M142.5 87.2v-2.3h2.7v2.3"/>
<path d="M142.5 88.8v2.2h2.7v-2.2M142.8 80.5v3.7M144.9 80.5v3.7M145.5 87.2v-2.3h2.6v2.3M145.5 88.8v2.2h2.6v-2.2M145.8 80.5v3.7M147.9 80.5v3.7M148.4 87.2v-1.6h2.1v1.6M148.4 88.2v1.7h2.1v-1.7M151.1 86.9v-2.2h2.6v2.2M151.1 88.5v2.3h2.6v-2.3M152.9 80.5h-2.2v2.7h2.2"/>
<path d="M153.2 92.2h-2.2v2.7h2.2M153.5 96h-1.6v2.1h1.6M153.5 99.2h-1.6v2.1h1.6M154 84.8v5.3M154.5 96h1.6v2.1h-1.6M154.5 99.2h1.6v2.1h-1.6M154.5 80.5h2.3v2.7h-2.3M154.8 92.2h2.2v2.7h-2.2M156.7 84.8v5.3M115.6 106.1h1.1M116.2 105.6v1M124.3 113.1h1.6l-.8 1.3z"/>
<path d="M124.6 113.1v.2h1.1l-.1 .2h-.8l.1 .1h.6l-.4 .5-.2-.3h.3M130.6 101.8h-2.3v2.7h2.3M131.6 108.8v5.3M132.2 101.8h2.2v2.7h-2.2M134.3 108.8v5.3M134.6 108.8v5.3M137.2 108.8v5.3M137.5 108.8v5.3M140.1 108.8v5.3M141.2 111.2v1.6h2.1v-1.6M141.2 110.1v-1.6h2.1v1.6M143.6 110.4v-2.3h2.7v2.3"/>
<path d="M143.6 112v2.2h2.7v-2.2M149.8 105.6h.3l-.2-.3-.3 .5h.6l.1 .2h-.8l-.1 .2h1v.2M149.9 113h6.1v2.7h-6.1zM149.9 107.2h6.1v2.6h-6.1zM149.9 105.1l.8 1.3h-1.6zM150.3 112.8h5.3M150.3 110.1h5.3M79.7 131.3h1.6l-.8 1.4zM79.9 131.3v.3h1.1l-.1 .2h-.8l.1 .1h.6l-.3 .5-.2-.3h.2M93 129.8h1M93.5 129.3v1M98.6 126.3v-2.2h2.6v2.2"/>
<path d="M101.2 128v2.2h-2.6v-2.2M102.6 127.1v-1.5h2.1v1.5M102.6 128.2v1.6h2.1v-1.6M103.9 139.4h-2.2v2.7h2.2M105.4 129.1l.2 .2-.1 .1 .7 .8-.2 .1-.6-.6v.2l.4 .4-.6 .1 .1-.4 .2 .2M105.4 129.1l1.2 1.1-1.6 .4zM105.5 139.4h2.2v2.7h-2.2M130.6 134.1h1M131.1 133.5v1.1M137.8 125.6l1.3 .8-1.3 .9zM138.5 126.4v.3l.4-.3-.5-.3v.6l-.2 .1v-.8l-.2-.1v1.1h-.2M141.5 139.1h-1.6v2.2h1.6"/>
<path d="M142.5 139.1h1.6v2.2h-1.6M154.3 122.1h1M154.8 121.6v1M171.3 128.9l1.4-.8v1.6zM172.7 128.3h-.2v1.1l-.2-.1v-.8l-.2 .1v.6l-.5-.3 .3-.2v.2M55.1 147l1.4 .8-1.4 .8zM55.9 147.8v.2l.3-.2-.5-.3v.6l-.2 .1v-.8l-.2-.1v1.1h-.2M72.9 149.5h6.1v2.7h-6.1zM72.9 153h6.1v2.7h-6.1zM72.9 156.5h6.1v2.6h-6.1zM72.9 159.7h6.1v2.6h-6.1zM81 157.3h-1.6v2.1h1.6"/>
<path d="M81 159.7h-1.6v2.1h1.6M82.1 159.7h1.6v2.1h-1.6M82.1 157.3h1.6v2.1h-1.6M90.8 149.5v1.6h2.2v-1.6M90.8 148.5v-1.6h2.2v1.6M93.3 149.5v1.6h2.1v-1.6M93.3 148.5v-1.6h2.1v1.6M97 149.5v1.6h2.1v-1.6M97 148.5v-1.6h2.1v1.6M98.3 143.2v2.2h2.7v-2.2M98.3 141.5v-2.2h2.7v2.2M103.9 143.2h-1.6v2.1h1.6"/>
<path d="M104.2 148.5v-1.6h2.1v1.6M104.2 149.5v1.6h2.1v-1.6M105 143.2h1.6v2.1h-1.6M107.4 148.5v-1.6h2.1v1.6M107.4 149.5v1.6h2.1v-1.6M111.1 149.5v1.6h2.1v-1.6M111.1 148.5v-1.6h2.1v1.6M119.6 156.7h-1.6v2.2h1.6M119.6 159.4h-1.6v2.1h1.6M120.7 159.4h1.6v2.1h-1.6M120.7 156.7h1.6v2.2h-1.6M139 142.6h6.1v2.7h-6.1z"/>
<path d="M67.8 176.4v6.4M70.6 164.6h2.7v6.1h-2.7zM70.7 176.4v6.4M70.9 175.6h1M71.4 175.1v1.1M73.7 164.5v6.4M76.2 171.1h-1.6v2.1h1.6M76.6 164.5v6.4M77.3 171.1h1.6v2.1h-1.6M77.4 164.5v6.4M80.3 164.5v6.4M86.6 175.9v-1.6h2.1v1.6"/>
<path d="M86.6 177v1.6h2.1v-1.6M93.8 175.9v-1.6h2.1v1.6M93.8 177v1.6h2.1v-1.6M107.1 174.3h-1.6v2.1h1.6M108.2 174.3h1.6v2.1h-1.6M119.6 165h-1.6v2.1h1.6M120.7 165h1.6v2.1h-1.6M127.4 167.7h-1.6v2.1h1.6M127.4 170.1h-1.6v2.1h1.6M127.9 173.2h1M128.4 170.1h1.6v2.1h-1.6M128.4 167.7h1.6v2.1h-1.6"/>
<path d="M128.4 172.7v1.1M171.6 174.7l1.4-.8v1.6zM173 174.2h-.3v1l-.2-.1v-.8l-.1 .1v.6l-.5-.3 .3-.2v.3M57.3 183.9v5.3M59.9 183.9v5.3M61.6 183.9v5.3M64.2 183.9v5.3M64.6 189l1.1 1.1-1.5 .4zM64.8 189.2l-.2 .1 .8 .8-.2 .1-.6-.6v.2l.4 .4-.6 .1 .1-.4 .2 .2M74.1 183.9h-2.3v2.7h2.3M74.3 187.1h-1.6v2.1h1.6M75.4 187.1h1.6v2.1h-1.6"/>
<path d="M75.7 183.9h2.2v2.7h-2.2M75.9 192.4v5.4M78.6 192.4v5.4M129.3 198.8v6.4M132.3 198.8v6.4M132.7 181h-1.6v2.1h1.6M133.8 181h1.6v2.1h-1.6M136.4 194.6h5.4M136.4 191.6h5.4M136.4 197.8h5.4M136.4 197.2h5.4M136.4 194.3h5.4"/>
<path d="M153.7 183l1.5 .4-1.1 1.2zM155.2 183.4l-.2 .2-.1-.1-.8 .7v-.2l.5-.6h-.2l-.4 .4-.1-.6 .4 .1-.2 .2M155.9 183.1h3.7M155.9 181h3.7M162.3 183.6h5.3M162.3 186.3h5.3M56.5 201.2h-2.2v2.7h2.2M58.1 201.2h2.2v2.7h-2.2M60.7 201.5v5.3M63.4 201.5v5.3M63.9 201.5v5.3M66.6 201.5v5.3"/>
<path d="M67.1 201.5v5.3M69.8 201.5v5.3M72.5 217.1h2.6v6.1h-2.6zM78.3 219.9h1.1M78.9 219.4v1M83.4 202v-1.6h2.1v1.6M83.4 203.1v1.6h2.1v-1.6M89 202v-1.6h2.1v1.6M89 203.1v1.6h2.1v-1.6M94.6 202v-1.6h2.1v1.6M94.6 203.1v1.6h2.1v-1.6M99.4 202v-1.6h2.1v1.6"/>
<path d="M99.4 203.1v1.6h2.1v-1.6M104.4 202v-1.6h2.2v1.6M104.4 203.1v1.6h2.2v-1.6M110 202v-1.6h4.3v1.6M110 203.1v1.6h4.3v-1.6M112.2 200.4v1.6M112.2 203.1v1.6M115.4 202v-1.6h2.1v1.6M115.4 203.1v1.6h2.1v-1.6M118 201.2h1.1M118 212.4h1.1M118.6 200.7v1.1"/>
<path d="M118.6 211.9v1.1M123.1 204.4h-1.6v2.2h1.6M123.1 207.6h-1.6v2.2h1.6M124.2 204.4h1.6v2.2h-1.6M124.2 207.6h1.6v2.2h-1.6M127.1 219.6h-2.2v2.7h2.2M128.7 219.6h2.2v2.7h-2.2M129.5 206v5.3M132.2 206v5.3M132.4 206.6v3.7M132.7 202v-1.6h2.1v1.6M132.7 203.1v1.6h2.1v-1.6"/>
<path d="M134.6 206.6v3.7M136.4 211.6h5.4M136.4 200.7h5.4M136.4 206.3h5.4M136.4 203.4h5.4h-5.4M136.4 200.4h5.4M136.4 206h5.4M141.8 209h-5.4h5.4M144.3 212.8h.2l-.2-.4-.3 .5h.6l.1 .2h-.8l-.1 .2h1v.2M144.3 212.2l.8 1.3h-1.6zM57.9 225.3l1.3 .8-1.3 .8zM58.7 226.1v.2l.3-.2-.5-.3v.6l-.2 .1v-.8l-.2-.1v1.1h-.2"/>
<path d="M67.9 220.9h1.1M68.5 220.4v1.1M73 225.5v-1.6h2.1v1.6M73 226.5v1.6h2.1v-1.6M120.2 230.5h-1.6v2.2h1.6M120.2 238.3h-1.6v2.1h1.6M120.2 232.9h-1.6v2.2h1.6M120.2 235.6h-1.6v2.1h1.6M120.2 227.9h-1.6v2.1h1.6M120.2 225.2h-1.6v2.2h1.6M120.2 222.5h-1.6v2.2h1.6M121.2 230.5h1.6v2.2h-1.6"/>
<path d="M121.2 222.5h1.6v2.2h-1.6M121.2 225.2h1.6v2.2h-1.6M121.2 227.9h1.6v2.1h-1.6M121.2 232.9h1.6v2.2h-1.6M121.2 235.6h1.6v2.1h-1.6M121.2 238.3h1.6v2.1h-1.6M124.9 239.1h6v2.6h-6zM125.2 232.7h5.4M125.2 225.7h5.4M125.2 235.9h5.4M125.2 235.3h5.4M125.2 228.4h5.4"/>
<path d="M125.2 238.5h5.4M127.1 222.8h-2.2v2.7h2.2M128.7 222.8h2.2v2.7h-2.2M134.3 239.6v2.2h-2.7v-2.2M134.3 233.2v2.2h-2.7v-2.2M134.3 231.6v-2.2h-2.7v2.2M134.3 238v-2.2h-2.7v2.2M71.7 241.2h-1.6v2.1h1.6M72.7 241.2h1.6v2.1h-1.6M86.6 240.9v5.4M89.3 240.9v5.4M93.8 240.6h2.7v6h-2.7z"/>
<path d="M93.8 247h2.7v6h-2.7zM99.9 240.9v5.4M102.6 240.9v5.4M104.7 240.9v5.4M107.4 240.6h2.6v6h-2.6zM110.3 240.9v5.4M110.3 247.9v5.3M112.5 256.6h1.7l-.9 1.4zM112.8 256.6v.2h1.1l-.1 .2h-.8l.1 .2h.6l-.4 .5-.2-.3h.3M113 240.9v5.4M113 247.9v5.3M113.5 240.9v5.4"/>
<path d="M113.5 248.4v3.7M115.6 248.4v3.7M116.2 240.9v5.4M117.5 251.6v5.3M120.2 251.6v5.3M120.4 240.9h1.1M121 240.4v1.1M126.3 259.1h5.3M131.9 251.6v5.3M132.4 259.1h5.4M134.6 251.6v5.3M135.1 251.6v5.3"/>
<path d="M137.8 251.6v5.3M148.4 251.9v3.7M150.1 249.5h.3l-.2-.3-.3 .5h.6l.1 .2h-.8l-.2 .2h1.1v.2h.3M150.2 248.9l.8 1.4h-1.6zM150.5 251.9v3.7M151.3 250.4v5.3M151.3 256.9v5.4M154 250.4v5.3M154 256.9v5.4M154.5 250.4v5.3M154.5 256.9v5.4M157.2 250.4v5.3"/>
<path d="M157.2 256.9v5.4M157.7 256.9v5.4M160.4 256.9v5.4M123.4 262v5.3M126 262v5.3M126.3 261.7h5.3M132.4 261.7h5.4M133.1 267.1h1.6l-.8 1.4zM133.3 267.1v.3h1.1l-.1 .2h-.8l.1 .1h.6l-.3 .5-.3-.3h.3M140.4 266h1.1M140.9 265.5v1M143.3 273.6l1.4 .8-1.4 .8z"/>
<path d="M144.1 274.3v.3l.3-.2-.5-.3v.6l-.2 .1v-.8l-.2-.1v1h-.2M145.6 265.8h.3l-.3-.3-.3 .5h.6l.1 .1h-.8l-.1 .2h1.1v.2M145.6 265.2l.8 1.3h-1.6zM154.4 263h6.1v2.7h-6.1z"/>
</g>
<g fill="none" stroke="#000" stroke-width=".28">
<path d="M55.1 36a2.61 2.61 0 0 0 0 2.7M60.5 36a2.56 2.56 0 0 1 0 2.7M61.8 36.3a2.69 2.69 0 0 1 2.7 0M83.9 31.5a2.61 2.61 0 0 0 0 2.6M89.2 31.5a2.49 2.49 0 0 1 0 2.6M93 31.5a2.61 2.61 0 0 0 0 2.6M98.3 31.5a2.49 2.49 0 0 1 0 2.6M112.2 36a2.61 2.61 0 0 1 2.6 0M114.8 36a2.61 2.61 0 0 1 2.7 0M117.5 36a2.61 2.61 0 0 1 2.6 0M118.8 33.1a2.33 2.33 0 0 0 0 2.1M120.4 36a2.61 2.61 0 0 1 2.7 0"/>
<path d="M122.6 33.1a2.21 2.21 0 0 1 0 2.1M123.4 36a2.61 2.61 0 0 1 2.6 0M135.1 35.8a2.61 2.61 0 0 0 0 2.6M140.4 35.8a2.49 2.49 0 0 1 0 2.6M140.9 35.2a2.56 2.56 0 0 0 2.7 0M140.9 29.9a2.61 2.61 0 0 1 2.7 0M141.7 39.5a2.69 2.69 0 0 1 2.7 0M145.2 39.5a2.69 2.69 0 0 1 2.7 0M61.8 42.7a2.69 2.69 0 0 1 2.7 0M61.8 41.6a2.56 2.56 0 0 0 2.7 0M61.8 48a2.56 2.56 0 0 0 2.7 0M107.9 56a2.49 2.49 0 0 0 2.7 0"/>
<path d="M107.9 57.1a2.61 2.61 0 0 1 2.7 0M107.9 50.7a2.61 2.61 0 0 1 2.7 0M108.2 42.7a2.65 2.65 0 0 1 2.6 0M108.2 48a2.52 2.52 0 0 0 2.6 0M112.2 41.3a2.49 2.49 0 0 0 2.6 0M114.8 41.3a2.49 2.49 0 0 0 2.7 0M117.5 41.3a2.49 2.49 0 0 0 2.6 0M120.4 41.3a2.49 2.49 0 0 0 2.7 0M123.4 41.3a2.49 2.49 0 0 0 2.6 0M125.5 42.4a2.61 2.61 0 0 1 2.6 0M125.5 47.7a2.49 2.49 0 0 0 2.6 0M133.2 48a2.69 2.69 0 0 0 0 2.7"/>
<path d="M134 56.3a2.69 2.69 0 0 0 0 2.6M138.5 48a2.49 2.49 0 0 1 0 2.7M139.3 56.3a2.56 2.56 0 0 1 0 2.6M141.7 44.8a2.56 2.56 0 0 0 2.7 0M145.2 44.8a2.56 2.56 0 0 0 2.7 0M159.9 50.4a2.69 2.69 0 0 0 0 2.7M165.2 50.4a2.49 2.49 0 0 1 0 2.7M167.3 50.4a2.61 2.61 0 0 0 0 2.7M172.6 50.4a2.49 2.49 0 0 1 0 2.7M57 77.9a2.21 2.21 0 0 0 2.1 0M57 74.1a2.29 2.29 0 0 1 2.1 0M63.1 78.7a2.56 2.56 0 0 0 2.7 0"/>
<path d="M63.1 73.3a2.61 2.61 0 0 1 2.7 0M70.3 77.1a2.57 2.57 0 0 0 0 2.6M75.6 77.1a2.45 2.45 0 0 1 0 2.6M107.9 62.4a2.56 2.56 0 0 0 2.7 0M111.9 76.5a2.26 2.26 0 0 0 2.1 0M111.9 72.8a2.33 2.33 0 0 1 2.1 0M114.3 77.3a2.56 2.56 0 0 0 2.7 0M114.3 72a2.61 2.61 0 0 1 2.6 0M128.4 77.3a2.52 2.52 0 0 0 2.7 0 2.52 2.52 0 0 0 2.6 0 2.56 2.56 0 0 0 2.7 0M128.4 72a2.65 2.65 0 0 1 2.7 0 2.65 2.65 0 0 1 2.7 0 2.61 2.61 0 0 1 2.6 0M136.4 77.3a2.56 2.56 0 0 0 2.7 0M136.4 72a2.61 2.61 0 0 1 2.7 0"/>
<path d="M82 88.2a2.69 2.69 0 0 0 0 2.7M87.4 88.2a2.49 2.49 0 0 1 0 2.7M93.2 80.2a2.38 2.38 0 0 1 2.2 0M93.3 84a2.13 2.13 0 0 0 2.1 0M142.8 84.2a2.26 2.26 0 0 0 2.1 0M142.8 80.5a2.33 2.33 0 0 1 2.1 0M145.7 84.2a2.21 2.21 0 0 0 2.2 0M145.8 80.5a2.29 2.29 0 0 1 2 0M154 84.8a2.69 2.69 0 0 1 2.7 0M154 90.1a2.56 2.56 0 0 0 2.7 0M131.6 114.1a2.56 2.56 0 0 0 2.7 0M131.6 108.8a2.69 2.69 0 0 1 2.7 0"/>
<path d="M134.5 114.1a2.56 2.56 0 0 0 2.7 0M134.5 108.8a2.69 2.69 0 0 1 2.7 0M137.5 108.8a2.69 2.69 0 0 1 2.6 0M137.5 114.1a2.56 2.56 0 0 0 2.6 0M150.3 110.1a2.65 2.65 0 0 0 0 2.7M155.6 110.1a2.52 2.52 0 0 1 0 2.7M57.3 183.9a2.69 2.69 0 0 1 2.6 0M57.3 189.2a2.56 2.56 0 0 0 2.6 0M61.5 183.9a2.65 2.65 0 0 1 2.7 0M61.5 189.2a2.52 2.52 0 0 0 2.7 0M75.9 197.8a2.56 2.56 0 0 0 2.7 0M75.9 192.4a2.61 2.61 0 0 1 2.7 0"/>
<path d="M136.4 197.8a2.61 2.61 0 0 0 0 2.6M136.4 194.6a2.61 2.61 0 0 0 0 2.6M136.4 191.6a2.61 2.61 0 0 0 0 2.7M141.7 197.8a2.49 2.49 0 0 1 0 2.6M141.7 194.6a2.49 2.49 0 0 1 0 2.6M141.7 191.6a2.49 2.49 0 0 1 0 2.7M155.9 181a2.42 2.42 0 0 0 0 2.1M159.6 181a2.26 2.26 0 0 1 0 2.1M162.3 183.6a2.61 2.61 0 0 0 0 2.7M167.6 183.6a2.49 2.49 0 0 1 0 2.7M60.7 206.8a2.56 2.56 0 0 0 2.7 0M60.7 201.5a2.61 2.61 0 0 1 2.7 0"/>
<path d="M63.9 206.8a2.56 2.56 0 0 0 2.7 0M63.9 201.5a2.61 2.61 0 0 1 2.7 0M67.1 206.8a2.56 2.56 0 0 0 2.7 0M67.1 201.5a2.61 2.61 0 0 1 2.7 0M129.5 211.3a2.56 2.56 0 0 0 2.7 0M129.5 206a2.61 2.61 0 0 1 2.6 0M132.4 206.5a2.42 2.42 0 0 1 2.2 0M132.4 210.3a2.17 2.17 0 0 0 2.1 0M136.4 209a2.61 2.61 0 0 0 0 2.6M136.4 200.7a2.61 2.61 0 0 0 0 2.6 2.61 2.61 0 0 0 0 2.7M136.4 206.3a2.61 2.61 0 0 0 0 2.6M141.7 209a2.49 2.49 0 0 1 0 2.6"/>
<path d="M141.7 200.7a2.49 2.49 0 0 1 0 2.6 2.49 2.49 0 0 1 0 2.7M141.7 206.3a2.49 2.49 0 0 1 0 2.6M125.2 235.9a2.61 2.61 0 0 0 0 2.6M125.2 232.7a2.61 2.61 0 0 0 0 2.6M125.2 225.7a2.61 2.61 0 0 0 0 2.7M130.5 235.9a2.49 2.49 0 0 1 0 2.6M130.5 232.7a2.49 2.49 0 0 1 0 2.6M130.5 225.7a2.49 2.49 0 0 1 0 2.7M86.6 246.3a2.56 2.56 0 0 0 2.7 0M86.6 240.9a2.69 2.69 0 0 1 2.7 0M99.9 240.9a2.69 2.69 0 0 1 2.7 0M99.9 246.3a2.56 2.56 0 0 0 2.7 0"/>
<path d="M104.7 240.9a2.69 2.69 0 0 1 2.7 0M104.7 246.3a2.56 2.56 0 0 0 2.7 0M110.3 247.8a2.69 2.69 0 0 1 2.7 0M110.3 240.9a2.69 2.69 0 0 1 2.7 0M110.3 246.3a2.56 2.56 0 0 0 2.7 0M110.3 253.2a2.49 2.49 0 0 0 2.6 0M113.5 240.9a2.69 2.69 0 0 1 2.7 0M113.5 246.3a2.56 2.56 0 0 0 2.7 0M113.5 248.4a2.38 2.38 0 0 1 2.1 0M113.5 252.1a2.21 2.21 0 0 0 2.1 0M117.5 256.9a2.49 2.49 0 0 0 2.6 0M117.5 251.6a2.61 2.61 0 0 1 2.6 0"/>
<path d="M126.3 259a2.65 2.65 0 0 0 0 2.7M131.6 259a2.52 2.52 0 0 1 0 2.7M131.9 256.9a2.49 2.49 0 0 0 2.6 0M131.9 251.6a2.61 2.61 0 0 1 2.6 0M132.4 259.1a2.57 2.57 0 0 0 0 2.6M135.1 251.6a2.61 2.61 0 0 1 2.6 0M135.1 256.9a2.49 2.49 0 0 0 2.6 0M137.7 259.1a2.45 2.45 0 0 1 0 2.6M148.4 251.8a2.38 2.38 0 0 1 2.1 0M148.4 255.6a2.17 2.17 0 0 0 2.1 0M151.3 250.4a2.69 2.69 0 0 1 2.7 0M151.3 256.9a2.69 2.69 0 0 1 2.7 0"/>
<path d="M151.3 255.7a2.56 2.56 0 0 0 2.7 0M154.5 256.9a2.69 2.69 0 0 1 2.7 0M154.5 250.4a2.69 2.69 0 0 1 2.7 0M154.5 255.7a2.56 2.56 0 0 0 2.7 0M157.7 256.9a2.69 2.69 0 0 1 2.7 0M123.4 267.3a2.49 2.49 0 0 0 2.6 0M123.4 262a2.61 2.61 0 0 1 2.6 0M151.3 262.2a2.49 2.49 0 0 0 2.7 0M154.5 262.2a2.49 2.49 0 0 0 2.7 0M157.7 262.2a2.49 2.49 0 0 0 2.7 0"/>
</g>
<path d="M76.7 31.8v2.1M149.5 113.3v2.1M154 263.3v2.2" fill="none" stroke="#000" stroke-width=".63"/>
<path d="M135.1 99.2h.2M137.4 93.6h-.5v.4M143.6 92v.2M148.8 93.6h.4v.4M136.9 105.4v.4h.5M142.6 107.4v.3M149.2 105.3l-.5 .5M150.6 100.2h.2M87.1 154.1h27.7v17h-27.7z" fill="none" stroke="#000" stroke-width=".3"/>
<path d="M123.6 149.3h3v2.9h-3zM123.6 153.5h3v3h-3z" fill="none" stroke="#000" stroke-width=".53"/>
<use href="#words"/>
</svg>
